VERSION 5.8 ;
BUSBITCHARS "[]" ;
DIVIDERCHAR "/" ;
UNITS
    DATABASE MICRONS 1000 ;
END UNITS

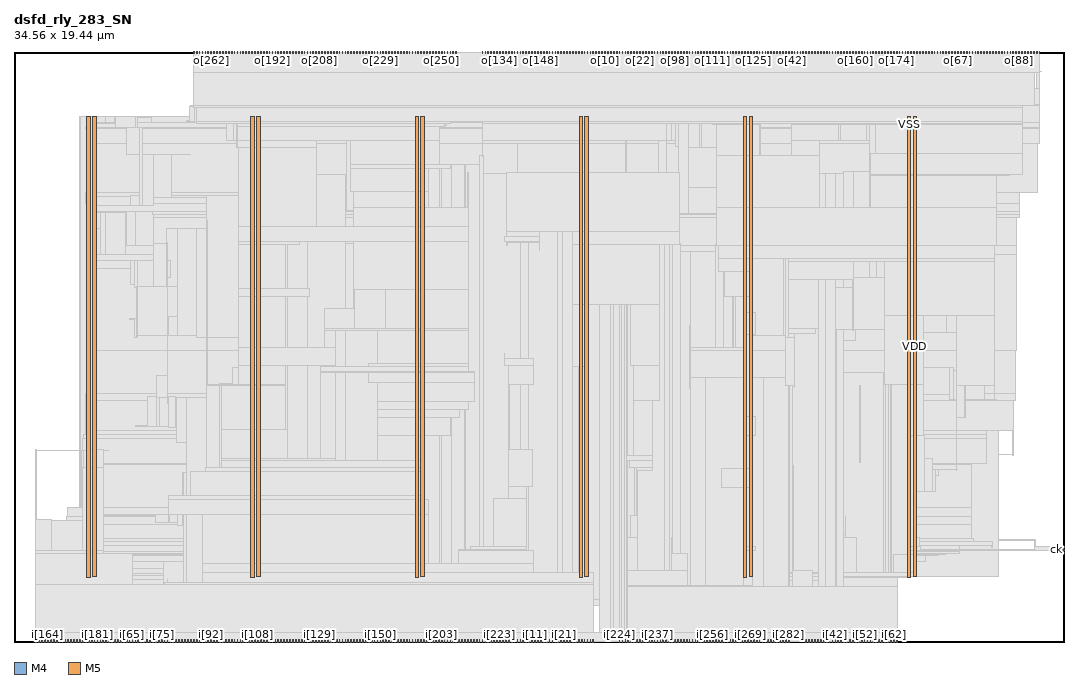
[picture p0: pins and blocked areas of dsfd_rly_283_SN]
MACRO dsfd_rly_283_SN
  FOREIGN dsfd_rly_283_SN 0 0 ;
  CLASS BLOCK ;
  SIZE 34.56 BY 19.44 ;
  PIN ck
    DIRECTION INPUT ;
    USE SIGNAL ;
    PORT
      LAYER M4 ;
        RECT  34.476 3.024 34.56 3.048 ;
    END
  END ck
  PIN i[0]
    DIRECTION INPUT ;
    USE SIGNAL ;
    PORT
      LAYER M5 ;
        RECT  16.08 0 16.104 0.084 ;
    END
  END i[0]
  PIN i[100]
    DIRECTION INPUT ;
    USE SIGNAL ;
    PORT
      LAYER M5 ;
        RECT  7.248 0 7.272 0.084 ;
    END
  END i[100]
  PIN i[101]
    DIRECTION INPUT ;
    USE SIGNAL ;
    PORT
      LAYER M5 ;
        RECT  7.344 0 7.368 0.084 ;
    END
  END i[101]
  PIN i[102]
    DIRECTION INPUT ;
    USE SIGNAL ;
    PORT
      LAYER M5 ;
        RECT  7.44 0 7.464 0.084 ;
    END
  END i[102]
  PIN i[103]
    DIRECTION INPUT ;
    USE SIGNAL ;
    PORT
      LAYER M5 ;
        RECT  7.536 0 7.56 0.084 ;
    END
  END i[103]
  PIN i[104]
    DIRECTION INPUT ;
    USE SIGNAL ;
    PORT
      LAYER M5 ;
        RECT  7.632 0 7.656 0.084 ;
    END
  END i[104]
  PIN i[105]
    DIRECTION INPUT ;
    USE SIGNAL ;
    PORT
      LAYER M5 ;
        RECT  7.728 0 7.752 0.084 ;
    END
  END i[105]
  PIN i[106]
    DIRECTION INPUT ;
    USE SIGNAL ;
    PORT
      LAYER M5 ;
        RECT  7.824 0 7.848 0.084 ;
    END
  END i[106]
  PIN i[107]
    DIRECTION INPUT ;
    USE SIGNAL ;
    PORT
      LAYER M5 ;
        RECT  7.92 0 7.944 0.084 ;
    END
  END i[107]
  PIN i[108]
    DIRECTION INPUT ;
    USE SIGNAL ;
    PORT
      LAYER M5 ;
        RECT  8.016 0 8.04 0.084 ;
    END
  END i[108]
  PIN i[109]
    DIRECTION INPUT ;
    USE SIGNAL ;
    PORT
      LAYER M5 ;
        RECT  8.112 0 8.136 0.084 ;
    END
  END i[109]
  PIN i[10]
    DIRECTION INPUT ;
    USE SIGNAL ;
    PORT
      LAYER M5 ;
        RECT  17.04 0 17.064 0.084 ;
    END
  END i[10]
  PIN i[110]
    DIRECTION INPUT ;
    USE SIGNAL ;
    PORT
      LAYER M5 ;
        RECT  8.208 0 8.232 0.084 ;
    END
  END i[110]
  PIN i[111]
    DIRECTION INPUT ;
    USE SIGNAL ;
    PORT
      LAYER M5 ;
        RECT  8.304 0 8.328 0.084 ;
    END
  END i[111]
  PIN i[112]
    DIRECTION INPUT ;
    USE SIGNAL ;
    PORT
      LAYER M5 ;
        RECT  8.4 0 8.424 0.084 ;
    END
  END i[112]
  PIN i[113]
    DIRECTION INPUT ;
    USE SIGNAL ;
    PORT
      LAYER M5 ;
        RECT  8.496 0 8.52 0.084 ;
    END
  END i[113]
  PIN i[114]
    DIRECTION INPUT ;
    USE SIGNAL ;
    PORT
      LAYER M5 ;
        RECT  8.592 0 8.616 0.084 ;
    END
  END i[114]
  PIN i[115]
    DIRECTION INPUT ;
    USE SIGNAL ;
    PORT
      LAYER M5 ;
        RECT  8.688 0 8.712 0.084 ;
    END
  END i[115]
  PIN i[116]
    DIRECTION INPUT ;
    USE SIGNAL ;
    PORT
      LAYER M5 ;
        RECT  8.784 0 8.808 0.084 ;
    END
  END i[116]
  PIN i[117]
    DIRECTION INPUT ;
    USE SIGNAL ;
    PORT
      LAYER M5 ;
        RECT  8.88 0 8.904 0.084 ;
    END
  END i[117]
  PIN i[118]
    DIRECTION INPUT ;
    USE SIGNAL ;
    PORT
      LAYER M5 ;
        RECT  8.976 0 9 0.084 ;
    END
  END i[118]
  PIN i[119]
    DIRECTION INPUT ;
    USE SIGNAL ;
    PORT
      LAYER M5 ;
        RECT  9.072 0 9.096 0.084 ;
    END
  END i[119]
  PIN i[11]
    DIRECTION INPUT ;
    USE SIGNAL ;
    PORT
      LAYER M5 ;
        RECT  17.136 0 17.16 0.084 ;
    END
  END i[11]
  PIN i[120]
    DIRECTION INPUT ;
    USE SIGNAL ;
    PORT
      LAYER M5 ;
        RECT  9.168 0 9.192 0.084 ;
    END
  END i[120]
  PIN i[121]
    DIRECTION INPUT ;
    USE SIGNAL ;
    PORT
      LAYER M5 ;
        RECT  9.264 0 9.288 0.084 ;
    END
  END i[121]
  PIN i[122]
    DIRECTION INPUT ;
    USE SIGNAL ;
    PORT
      LAYER M5 ;
        RECT  9.36 0 9.384 0.084 ;
    END
  END i[122]
  PIN i[123]
    DIRECTION INPUT ;
    USE SIGNAL ;
    PORT
      LAYER M5 ;
        RECT  9.456 0 9.48 0.084 ;
    END
  END i[123]
  PIN i[124]
    DIRECTION INPUT ;
    USE SIGNAL ;
    PORT
      LAYER M5 ;
        RECT  9.552 0 9.576 0.084 ;
    END
  END i[124]
  PIN i[125]
    DIRECTION INPUT ;
    USE SIGNAL ;
    PORT
      LAYER M5 ;
        RECT  9.648 0 9.672 0.084 ;
    END
  END i[125]
  PIN i[126]
    DIRECTION INPUT ;
    USE SIGNAL ;
    PORT
      LAYER M5 ;
        RECT  9.744 0 9.768 0.084 ;
    END
  END i[126]
  PIN i[127]
    DIRECTION INPUT ;
    USE SIGNAL ;
    PORT
      LAYER M5 ;
        RECT  9.84 0 9.864 0.084 ;
    END
  END i[127]
  PIN i[128]
    DIRECTION INPUT ;
    USE SIGNAL ;
    PORT
      LAYER M5 ;
        RECT  9.936 0 9.96 0.084 ;
    END
  END i[128]
  PIN i[129]
    DIRECTION INPUT ;
    USE SIGNAL ;
    PORT
      LAYER M5 ;
        RECT  10.032 0 10.056 0.084 ;
    END
  END i[129]
  PIN i[12]
    DIRECTION INPUT ;
    USE SIGNAL ;
    PORT
      LAYER M5 ;
        RECT  17.232 0 17.256 0.084 ;
    END
  END i[12]
  PIN i[130]
    DIRECTION INPUT ;
    USE SIGNAL ;
    PORT
      LAYER M5 ;
        RECT  10.128 0 10.152 0.084 ;
    END
  END i[130]
  PIN i[131]
    DIRECTION INPUT ;
    USE SIGNAL ;
    PORT
      LAYER M5 ;
        RECT  10.224 0 10.248 0.084 ;
    END
  END i[131]
  PIN i[132]
    DIRECTION INPUT ;
    USE SIGNAL ;
    PORT
      LAYER M5 ;
        RECT  10.32 0 10.344 0.084 ;
    END
  END i[132]
  PIN i[133]
    DIRECTION INPUT ;
    USE SIGNAL ;
    PORT
      LAYER M5 ;
        RECT  10.416 0 10.44 0.084 ;
    END
  END i[133]
  PIN i[134]
    DIRECTION INPUT ;
    USE SIGNAL ;
    PORT
      LAYER M5 ;
        RECT  10.512 0 10.536 0.084 ;
    END
  END i[134]
  PIN i[135]
    DIRECTION INPUT ;
    USE SIGNAL ;
    PORT
      LAYER M5 ;
        RECT  10.608 0 10.632 0.084 ;
    END
  END i[135]
  PIN i[136]
    DIRECTION INPUT ;
    USE SIGNAL ;
    PORT
      LAYER M5 ;
        RECT  10.704 0 10.728 0.084 ;
    END
  END i[136]
  PIN i[137]
    DIRECTION INPUT ;
    USE SIGNAL ;
    PORT
      LAYER M5 ;
        RECT  10.8 0 10.824 0.084 ;
    END
  END i[137]
  PIN i[138]
    DIRECTION INPUT ;
    USE SIGNAL ;
    PORT
      LAYER M5 ;
        RECT  10.896 0 10.92 0.084 ;
    END
  END i[138]
  PIN i[139]
    DIRECTION INPUT ;
    USE SIGNAL ;
    PORT
      LAYER M5 ;
        RECT  10.992 0 11.016 0.084 ;
    END
  END i[139]
  PIN i[13]
    DIRECTION INPUT ;
    USE SIGNAL ;
    PORT
      LAYER M5 ;
        RECT  17.328 0 17.352 0.084 ;
    END
  END i[13]
  PIN i[140]
    DIRECTION INPUT ;
    USE SIGNAL ;
    PORT
      LAYER M5 ;
        RECT  11.088 0 11.112 0.084 ;
    END
  END i[140]
  PIN i[141]
    DIRECTION INPUT ;
    USE SIGNAL ;
    PORT
      LAYER M5 ;
        RECT  11.184 0 11.208 0.084 ;
    END
  END i[141]
  PIN i[142]
    DIRECTION INPUT ;
    USE SIGNAL ;
    PORT
      LAYER M5 ;
        RECT  11.28 0 11.304 0.084 ;
    END
  END i[142]
  PIN i[143]
    DIRECTION INPUT ;
    USE SIGNAL ;
    PORT
      LAYER M5 ;
        RECT  11.376 0 11.4 0.084 ;
    END
  END i[143]
  PIN i[144]
    DIRECTION INPUT ;
    USE SIGNAL ;
    PORT
      LAYER M5 ;
        RECT  11.472 0 11.496 0.084 ;
    END
  END i[144]
  PIN i[145]
    DIRECTION INPUT ;
    USE SIGNAL ;
    PORT
      LAYER M5 ;
        RECT  11.568 0 11.592 0.084 ;
    END
  END i[145]
  PIN i[146]
    DIRECTION INPUT ;
    USE SIGNAL ;
    PORT
      LAYER M5 ;
        RECT  11.664 0 11.688 0.084 ;
    END
  END i[146]
  PIN i[147]
    DIRECTION INPUT ;
    USE SIGNAL ;
    PORT
      LAYER M5 ;
        RECT  11.76 0 11.784 0.084 ;
    END
  END i[147]
  PIN i[148]
    DIRECTION INPUT ;
    USE SIGNAL ;
    PORT
      LAYER M5 ;
        RECT  11.856 0 11.88 0.084 ;
    END
  END i[148]
  PIN i[149]
    DIRECTION INPUT ;
    USE SIGNAL ;
    PORT
      LAYER M5 ;
        RECT  11.952 0 11.976 0.084 ;
    END
  END i[149]
  PIN i[14]
    DIRECTION INPUT ;
    USE SIGNAL ;
    PORT
      LAYER M5 ;
        RECT  17.424 0 17.448 0.084 ;
    END
  END i[14]
  PIN i[150]
    DIRECTION INPUT ;
    USE SIGNAL ;
    PORT
      LAYER M5 ;
        RECT  12.048 0 12.072 0.084 ;
    END
  END i[150]
  PIN i[151]
    DIRECTION INPUT ;
    USE SIGNAL ;
    PORT
      LAYER M5 ;
        RECT  12.144 0 12.168 0.084 ;
    END
  END i[151]
  PIN i[152]
    DIRECTION INPUT ;
    USE SIGNAL ;
    PORT
      LAYER M5 ;
        RECT  12.24 0 12.264 0.084 ;
    END
  END i[152]
  PIN i[153]
    DIRECTION INPUT ;
    USE SIGNAL ;
    PORT
      LAYER M5 ;
        RECT  12.336 0 12.36 0.084 ;
    END
  END i[153]
  PIN i[154]
    DIRECTION INPUT ;
    USE SIGNAL ;
    PORT
      LAYER M5 ;
        RECT  12.432 0 12.456 0.084 ;
    END
  END i[154]
  PIN i[155]
    DIRECTION INPUT ;
    USE SIGNAL ;
    PORT
      LAYER M5 ;
        RECT  12.528 0 12.552 0.084 ;
    END
  END i[155]
  PIN i[156]
    DIRECTION INPUT ;
    USE SIGNAL ;
    PORT
      LAYER M5 ;
        RECT  12.624 0 12.648 0.084 ;
    END
  END i[156]
  PIN i[157]
    DIRECTION INPUT ;
    USE SIGNAL ;
    PORT
      LAYER M5 ;
        RECT  12.72 0 12.744 0.084 ;
    END
  END i[157]
  PIN i[158]
    DIRECTION INPUT ;
    USE SIGNAL ;
    PORT
      LAYER M5 ;
        RECT  12.816 0 12.84 0.084 ;
    END
  END i[158]
  PIN i[159]
    DIRECTION INPUT ;
    USE SIGNAL ;
    PORT
      LAYER M5 ;
        RECT  12.912 0 12.936 0.084 ;
    END
  END i[159]
  PIN i[15]
    DIRECTION INPUT ;
    USE SIGNAL ;
    PORT
      LAYER M5 ;
        RECT  17.52 0 17.544 0.084 ;
    END
  END i[15]
  PIN i[160]
    DIRECTION INPUT ;
    USE SIGNAL ;
    PORT
      LAYER M5 ;
        RECT  0.72 0 0.744 0.084 ;
    END
  END i[160]
  PIN i[161]
    DIRECTION INPUT ;
    USE SIGNAL ;
    PORT
      LAYER M5 ;
        RECT  0.816 0 0.84 0.084 ;
    END
  END i[161]
  PIN i[162]
    DIRECTION INPUT ;
    USE SIGNAL ;
    PORT
      LAYER M5 ;
        RECT  0.912 0 0.936 0.084 ;
    END
  END i[162]
  PIN i[163]
    DIRECTION INPUT ;
    USE SIGNAL ;
    PORT
      LAYER M5 ;
        RECT  1.008 0 1.032 0.084 ;
    END
  END i[163]
  PIN i[164]
    DIRECTION INPUT ;
    USE SIGNAL ;
    PORT
      LAYER M5 ;
        RECT  1.104 0 1.128 0.084 ;
    END
  END i[164]
  PIN i[165]
    DIRECTION INPUT ;
    USE SIGNAL ;
    PORT
      LAYER M5 ;
        RECT  1.2 0 1.224 0.084 ;
    END
  END i[165]
  PIN i[166]
    DIRECTION INPUT ;
    USE SIGNAL ;
    PORT
      LAYER M5 ;
        RECT  1.296 0 1.32 0.084 ;
    END
  END i[166]
  PIN i[167]
    DIRECTION INPUT ;
    USE SIGNAL ;
    PORT
      LAYER M5 ;
        RECT  1.392 0 1.416 0.084 ;
    END
  END i[167]
  PIN i[168]
    DIRECTION INPUT ;
    USE SIGNAL ;
    PORT
      LAYER M5 ;
        RECT  1.488 0 1.512 0.084 ;
    END
  END i[168]
  PIN i[169]
    DIRECTION INPUT ;
    USE SIGNAL ;
    PORT
      LAYER M5 ;
        RECT  1.584 0 1.608 0.084 ;
    END
  END i[169]
  PIN i[16]
    DIRECTION INPUT ;
    USE SIGNAL ;
    PORT
      LAYER M5 ;
        RECT  17.616 0 17.64 0.084 ;
    END
  END i[16]
  PIN i[170]
    DIRECTION INPUT ;
    USE SIGNAL ;
    PORT
      LAYER M5 ;
        RECT  1.68 0 1.704 0.084 ;
    END
  END i[170]
  PIN i[171]
    DIRECTION INPUT ;
    USE SIGNAL ;
    PORT
      LAYER M5 ;
        RECT  1.776 0 1.8 0.084 ;
    END
  END i[171]
  PIN i[172]
    DIRECTION INPUT ;
    USE SIGNAL ;
    PORT
      LAYER M5 ;
        RECT  1.872 0 1.896 0.084 ;
    END
  END i[172]
  PIN i[173]
    DIRECTION INPUT ;
    USE SIGNAL ;
    PORT
      LAYER M5 ;
        RECT  1.968 0 1.992 0.084 ;
    END
  END i[173]
  PIN i[174]
    DIRECTION INPUT ;
    USE SIGNAL ;
    PORT
      LAYER M5 ;
        RECT  2.064 0 2.088 0.084 ;
    END
  END i[174]
  PIN i[175]
    DIRECTION INPUT ;
    USE SIGNAL ;
    PORT
      LAYER M5 ;
        RECT  2.16 0 2.184 0.084 ;
    END
  END i[175]
  PIN i[176]
    DIRECTION INPUT ;
    USE SIGNAL ;
    PORT
      LAYER M5 ;
        RECT  2.256 0 2.28 0.084 ;
    END
  END i[176]
  PIN i[177]
    DIRECTION INPUT ;
    USE SIGNAL ;
    PORT
      LAYER M5 ;
        RECT  2.352 0 2.376 0.084 ;
    END
  END i[177]
  PIN i[178]
    DIRECTION INPUT ;
    USE SIGNAL ;
    PORT
      LAYER M5 ;
        RECT  2.448 0 2.472 0.084 ;
    END
  END i[178]
  PIN i[179]
    DIRECTION INPUT ;
    USE SIGNAL ;
    PORT
      LAYER M5 ;
        RECT  2.544 0 2.568 0.084 ;
    END
  END i[179]
  PIN i[17]
    DIRECTION INPUT ;
    USE SIGNAL ;
    PORT
      LAYER M5 ;
        RECT  17.712 0 17.736 0.084 ;
    END
  END i[17]
  PIN i[180]
    DIRECTION INPUT ;
    USE SIGNAL ;
    PORT
      LAYER M5 ;
        RECT  2.64 0 2.664 0.084 ;
    END
  END i[180]
  PIN i[181]
    DIRECTION INPUT ;
    USE SIGNAL ;
    PORT
      LAYER M5 ;
        RECT  2.736 0 2.76 0.084 ;
    END
  END i[181]
  PIN i[182]
    DIRECTION INPUT ;
    USE SIGNAL ;
    PORT
      LAYER M5 ;
        RECT  2.832 0 2.856 0.084 ;
    END
  END i[182]
  PIN i[183]
    DIRECTION INPUT ;
    USE SIGNAL ;
    PORT
      LAYER M5 ;
        RECT  2.928 0 2.952 0.084 ;
    END
  END i[183]
  PIN i[184]
    DIRECTION INPUT ;
    USE SIGNAL ;
    PORT
      LAYER M5 ;
        RECT  3.024 0 3.048 0.084 ;
    END
  END i[184]
  PIN i[185]
    DIRECTION INPUT ;
    USE SIGNAL ;
    PORT
      LAYER M5 ;
        RECT  3.12 0 3.144 0.084 ;
    END
  END i[185]
  PIN i[186]
    DIRECTION INPUT ;
    USE SIGNAL ;
    PORT
      LAYER M5 ;
        RECT  3.216 0 3.24 0.084 ;
    END
  END i[186]
  PIN i[187]
    DIRECTION INPUT ;
    USE SIGNAL ;
    PORT
      LAYER M5 ;
        RECT  3.312 0 3.336 0.084 ;
    END
  END i[187]
  PIN i[188]
    DIRECTION INPUT ;
    USE SIGNAL ;
    PORT
      LAYER M5 ;
        RECT  3.408 0 3.432 0.084 ;
    END
  END i[188]
  PIN i[189]
    DIRECTION INPUT ;
    USE SIGNAL ;
    PORT
      LAYER M5 ;
        RECT  3.504 0 3.528 0.084 ;
    END
  END i[189]
  PIN i[18]
    DIRECTION INPUT ;
    USE SIGNAL ;
    PORT
      LAYER M5 ;
        RECT  17.808 0 17.832 0.084 ;
    END
  END i[18]
  PIN i[190]
    DIRECTION INPUT ;
    USE SIGNAL ;
    PORT
      LAYER M5 ;
        RECT  3.6 0 3.624 0.084 ;
    END
  END i[190]
  PIN i[191]
    DIRECTION INPUT ;
    USE SIGNAL ;
    PORT
      LAYER M5 ;
        RECT  3.696 0 3.72 0.084 ;
    END
  END i[191]
  PIN i[192]
    DIRECTION INPUT ;
    USE SIGNAL ;
    PORT
      LAYER M5 ;
        RECT  13.008 0 13.032 0.084 ;
    END
  END i[192]
  PIN i[193]
    DIRECTION INPUT ;
    USE SIGNAL ;
    PORT
      LAYER M5 ;
        RECT  13.104 0 13.128 0.084 ;
    END
  END i[193]
  PIN i[194]
    DIRECTION INPUT ;
    USE SIGNAL ;
    PORT
      LAYER M5 ;
        RECT  13.2 0 13.224 0.084 ;
    END
  END i[194]
  PIN i[195]
    DIRECTION INPUT ;
    USE SIGNAL ;
    PORT
      LAYER M5 ;
        RECT  13.296 0 13.32 0.084 ;
    END
  END i[195]
  PIN i[196]
    DIRECTION INPUT ;
    USE SIGNAL ;
    PORT
      LAYER M5 ;
        RECT  13.392 0 13.416 0.084 ;
    END
  END i[196]
  PIN i[197]
    DIRECTION INPUT ;
    USE SIGNAL ;
    PORT
      LAYER M5 ;
        RECT  13.488 0 13.512 0.084 ;
    END
  END i[197]
  PIN i[198]
    DIRECTION INPUT ;
    USE SIGNAL ;
    PORT
      LAYER M5 ;
        RECT  13.584 0 13.608 0.084 ;
    END
  END i[198]
  PIN i[199]
    DIRECTION INPUT ;
    USE SIGNAL ;
    PORT
      LAYER M5 ;
        RECT  13.68 0 13.704 0.084 ;
    END
  END i[199]
  PIN i[19]
    DIRECTION INPUT ;
    USE SIGNAL ;
    PORT
      LAYER M5 ;
        RECT  17.904 0 17.928 0.084 ;
    END
  END i[19]
  PIN i[1]
    DIRECTION INPUT ;
    USE SIGNAL ;
    PORT
      LAYER M5 ;
        RECT  16.176 0 16.2 0.084 ;
    END
  END i[1]
  PIN i[200]
    DIRECTION INPUT ;
    USE SIGNAL ;
    PORT
      LAYER M5 ;
        RECT  13.776 0 13.8 0.084 ;
    END
  END i[200]
  PIN i[201]
    DIRECTION INPUT ;
    USE SIGNAL ;
    PORT
      LAYER M5 ;
        RECT  13.872 0 13.896 0.084 ;
    END
  END i[201]
  PIN i[202]
    DIRECTION INPUT ;
    USE SIGNAL ;
    PORT
      LAYER M5 ;
        RECT  13.968 0 13.992 0.084 ;
    END
  END i[202]
  PIN i[203]
    DIRECTION INPUT ;
    USE SIGNAL ;
    PORT
      LAYER M5 ;
        RECT  14.064 0 14.088 0.084 ;
    END
  END i[203]
  PIN i[204]
    DIRECTION INPUT ;
    USE SIGNAL ;
    PORT
      LAYER M5 ;
        RECT  14.16 0 14.184 0.084 ;
    END
  END i[204]
  PIN i[205]
    DIRECTION INPUT ;
    USE SIGNAL ;
    PORT
      LAYER M5 ;
        RECT  14.256 0 14.28 0.084 ;
    END
  END i[205]
  PIN i[206]
    DIRECTION INPUT ;
    USE SIGNAL ;
    PORT
      LAYER M5 ;
        RECT  14.352 0 14.376 0.084 ;
    END
  END i[206]
  PIN i[207]
    DIRECTION INPUT ;
    USE SIGNAL ;
    PORT
      LAYER M5 ;
        RECT  14.448 0 14.472 0.084 ;
    END
  END i[207]
  PIN i[208]
    DIRECTION INPUT ;
    USE SIGNAL ;
    PORT
      LAYER M5 ;
        RECT  14.544 0 14.568 0.084 ;
    END
  END i[208]
  PIN i[209]
    DIRECTION INPUT ;
    USE SIGNAL ;
    PORT
      LAYER M5 ;
        RECT  14.64 0 14.664 0.084 ;
    END
  END i[209]
  PIN i[20]
    DIRECTION INPUT ;
    USE SIGNAL ;
    PORT
      LAYER M5 ;
        RECT  18 0 18.024 0.084 ;
    END
  END i[20]
  PIN i[210]
    DIRECTION INPUT ;
    USE SIGNAL ;
    PORT
      LAYER M5 ;
        RECT  14.736 0 14.76 0.084 ;
    END
  END i[210]
  PIN i[211]
    DIRECTION INPUT ;
    USE SIGNAL ;
    PORT
      LAYER M5 ;
        RECT  14.832 0 14.856 0.084 ;
    END
  END i[211]
  PIN i[212]
    DIRECTION INPUT ;
    USE SIGNAL ;
    PORT
      LAYER M5 ;
        RECT  14.928 0 14.952 0.084 ;
    END
  END i[212]
  PIN i[213]
    DIRECTION INPUT ;
    USE SIGNAL ;
    PORT
      LAYER M5 ;
        RECT  15.024 0 15.048 0.084 ;
    END
  END i[213]
  PIN i[214]
    DIRECTION INPUT ;
    USE SIGNAL ;
    PORT
      LAYER M5 ;
        RECT  15.12 0 15.144 0.084 ;
    END
  END i[214]
  PIN i[215]
    DIRECTION INPUT ;
    USE SIGNAL ;
    PORT
      LAYER M5 ;
        RECT  15.216 0 15.24 0.084 ;
    END
  END i[215]
  PIN i[216]
    DIRECTION INPUT ;
    USE SIGNAL ;
    PORT
      LAYER M5 ;
        RECT  15.312 0 15.336 0.084 ;
    END
  END i[216]
  PIN i[217]
    DIRECTION INPUT ;
    USE SIGNAL ;
    PORT
      LAYER M5 ;
        RECT  15.408 0 15.432 0.084 ;
    END
  END i[217]
  PIN i[218]
    DIRECTION INPUT ;
    USE SIGNAL ;
    PORT
      LAYER M5 ;
        RECT  15.504 0 15.528 0.084 ;
    END
  END i[218]
  PIN i[219]
    DIRECTION INPUT ;
    USE SIGNAL ;
    PORT
      LAYER M5 ;
        RECT  15.6 0 15.624 0.084 ;
    END
  END i[219]
  PIN i[21]
    DIRECTION INPUT ;
    USE SIGNAL ;
    PORT
      LAYER M5 ;
        RECT  18.096 0 18.12 0.084 ;
    END
  END i[21]
  PIN i[220]
    DIRECTION INPUT ;
    USE SIGNAL ;
    PORT
      LAYER M5 ;
        RECT  15.696 0 15.72 0.084 ;
    END
  END i[220]
  PIN i[221]
    DIRECTION INPUT ;
    USE SIGNAL ;
    PORT
      LAYER M5 ;
        RECT  15.792 0 15.816 0.084 ;
    END
  END i[221]
  PIN i[222]
    DIRECTION INPUT ;
    USE SIGNAL ;
    PORT
      LAYER M5 ;
        RECT  15.888 0 15.912 0.084 ;
    END
  END i[222]
  PIN i[223]
    DIRECTION INPUT ;
    USE SIGNAL ;
    PORT
      LAYER M5 ;
        RECT  15.984 0 16.008 0.084 ;
    END
  END i[223]
  PIN i[224]
    DIRECTION INPUT ;
    USE SIGNAL ;
    PORT
      LAYER M5 ;
        RECT  19.92 0 19.944 0.084 ;
    END
  END i[224]
  PIN i[225]
    DIRECTION INPUT ;
    USE SIGNAL ;
    PORT
      LAYER M5 ;
        RECT  20.016 0 20.04 0.084 ;
    END
  END i[225]
  PIN i[226]
    DIRECTION INPUT ;
    USE SIGNAL ;
    PORT
      LAYER M5 ;
        RECT  20.112 0 20.136 0.084 ;
    END
  END i[226]
  PIN i[227]
    DIRECTION INPUT ;
    USE SIGNAL ;
    PORT
      LAYER M5 ;
        RECT  20.208 0 20.232 0.084 ;
    END
  END i[227]
  PIN i[228]
    DIRECTION INPUT ;
    USE SIGNAL ;
    PORT
      LAYER M5 ;
        RECT  20.304 0 20.328 0.084 ;
    END
  END i[228]
  PIN i[229]
    DIRECTION INPUT ;
    USE SIGNAL ;
    PORT
      LAYER M5 ;
        RECT  20.4 0 20.424 0.084 ;
    END
  END i[229]
  PIN i[22]
    DIRECTION INPUT ;
    USE SIGNAL ;
    PORT
      LAYER M5 ;
        RECT  18.192 0 18.216 0.084 ;
    END
  END i[22]
  PIN i[230]
    DIRECTION INPUT ;
    USE SIGNAL ;
    PORT
      LAYER M5 ;
        RECT  20.496 0 20.52 0.084 ;
    END
  END i[230]
  PIN i[231]
    DIRECTION INPUT ;
    USE SIGNAL ;
    PORT
      LAYER M5 ;
        RECT  20.592 0 20.616 0.084 ;
    END
  END i[231]
  PIN i[232]
    DIRECTION INPUT ;
    USE SIGNAL ;
    PORT
      LAYER M5 ;
        RECT  20.688 0 20.712 0.084 ;
    END
  END i[232]
  PIN i[233]
    DIRECTION INPUT ;
    USE SIGNAL ;
    PORT
      LAYER M5 ;
        RECT  20.784 0 20.808 0.084 ;
    END
  END i[233]
  PIN i[234]
    DIRECTION INPUT ;
    USE SIGNAL ;
    PORT
      LAYER M5 ;
        RECT  20.88 0 20.904 0.084 ;
    END
  END i[234]
  PIN i[235]
    DIRECTION INPUT ;
    USE SIGNAL ;
    PORT
      LAYER M5 ;
        RECT  20.976 0 21 0.084 ;
    END
  END i[235]
  PIN i[236]
    DIRECTION INPUT ;
    USE SIGNAL ;
    PORT
      LAYER M5 ;
        RECT  21.072 0 21.096 0.084 ;
    END
  END i[236]
  PIN i[237]
    DIRECTION INPUT ;
    USE SIGNAL ;
    PORT
      LAYER M5 ;
        RECT  21.168 0 21.192 0.084 ;
    END
  END i[237]
  PIN i[238]
    DIRECTION INPUT ;
    USE SIGNAL ;
    PORT
      LAYER M5 ;
        RECT  21.264 0 21.288 0.084 ;
    END
  END i[238]
  PIN i[239]
    DIRECTION INPUT ;
    USE SIGNAL ;
    PORT
      LAYER M5 ;
        RECT  21.36 0 21.384 0.084 ;
    END
  END i[239]
  PIN i[23]
    DIRECTION INPUT ;
    USE SIGNAL ;
    PORT
      LAYER M5 ;
        RECT  18.288 0 18.312 0.084 ;
    END
  END i[23]
  PIN i[240]
    DIRECTION INPUT ;
    USE SIGNAL ;
    PORT
      LAYER M5 ;
        RECT  21.456 0 21.48 0.084 ;
    END
  END i[240]
  PIN i[241]
    DIRECTION INPUT ;
    USE SIGNAL ;
    PORT
      LAYER M5 ;
        RECT  21.552 0 21.576 0.084 ;
    END
  END i[241]
  PIN i[242]
    DIRECTION INPUT ;
    USE SIGNAL ;
    PORT
      LAYER M5 ;
        RECT  21.648 0 21.672 0.084 ;
    END
  END i[242]
  PIN i[243]
    DIRECTION INPUT ;
    USE SIGNAL ;
    PORT
      LAYER M5 ;
        RECT  21.744 0 21.768 0.084 ;
    END
  END i[243]
  PIN i[244]
    DIRECTION INPUT ;
    USE SIGNAL ;
    PORT
      LAYER M5 ;
        RECT  21.84 0 21.864 0.084 ;
    END
  END i[244]
  PIN i[245]
    DIRECTION INPUT ;
    USE SIGNAL ;
    PORT
      LAYER M5 ;
        RECT  21.936 0 21.96 0.084 ;
    END
  END i[245]
  PIN i[246]
    DIRECTION INPUT ;
    USE SIGNAL ;
    PORT
      LAYER M5 ;
        RECT  22.032 0 22.056 0.084 ;
    END
  END i[246]
  PIN i[247]
    DIRECTION INPUT ;
    USE SIGNAL ;
    PORT
      LAYER M5 ;
        RECT  22.128 0 22.152 0.084 ;
    END
  END i[247]
  PIN i[248]
    DIRECTION INPUT ;
    USE SIGNAL ;
    PORT
      LAYER M5 ;
        RECT  22.224 0 22.248 0.084 ;
    END
  END i[248]
  PIN i[249]
    DIRECTION INPUT ;
    USE SIGNAL ;
    PORT
      LAYER M5 ;
        RECT  22.32 0 22.344 0.084 ;
    END
  END i[249]
  PIN i[24]
    DIRECTION INPUT ;
    USE SIGNAL ;
    PORT
      LAYER M5 ;
        RECT  18.384 0 18.408 0.084 ;
    END
  END i[24]
  PIN i[250]
    DIRECTION INPUT ;
    USE SIGNAL ;
    PORT
      LAYER M5 ;
        RECT  22.416 0 22.44 0.084 ;
    END
  END i[250]
  PIN i[251]
    DIRECTION INPUT ;
    USE SIGNAL ;
    PORT
      LAYER M5 ;
        RECT  22.512 0 22.536 0.084 ;
    END
  END i[251]
  PIN i[252]
    DIRECTION INPUT ;
    USE SIGNAL ;
    PORT
      LAYER M5 ;
        RECT  22.608 0 22.632 0.084 ;
    END
  END i[252]
  PIN i[253]
    DIRECTION INPUT ;
    USE SIGNAL ;
    PORT
      LAYER M5 ;
        RECT  22.704 0 22.728 0.084 ;
    END
  END i[253]
  PIN i[254]
    DIRECTION INPUT ;
    USE SIGNAL ;
    PORT
      LAYER M5 ;
        RECT  22.8 0 22.824 0.084 ;
    END
  END i[254]
  PIN i[255]
    DIRECTION INPUT ;
    USE SIGNAL ;
    PORT
      LAYER M5 ;
        RECT  22.896 0 22.92 0.084 ;
    END
  END i[255]
  PIN i[256]
    DIRECTION INPUT ;
    USE SIGNAL ;
    PORT
      LAYER M5 ;
        RECT  22.992 0 23.016 0.084 ;
    END
  END i[256]
  PIN i[257]
    DIRECTION INPUT ;
    USE SIGNAL ;
    PORT
      LAYER M5 ;
        RECT  23.088 0 23.112 0.084 ;
    END
  END i[257]
  PIN i[258]
    DIRECTION INPUT ;
    USE SIGNAL ;
    PORT
      LAYER M5 ;
        RECT  23.184 0 23.208 0.084 ;
    END
  END i[258]
  PIN i[259]
    DIRECTION INPUT ;
    USE SIGNAL ;
    PORT
      LAYER M5 ;
        RECT  23.28 0 23.304 0.084 ;
    END
  END i[259]
  PIN i[25]
    DIRECTION INPUT ;
    USE SIGNAL ;
    PORT
      LAYER M5 ;
        RECT  18.48 0 18.504 0.084 ;
    END
  END i[25]
  PIN i[260]
    DIRECTION INPUT ;
    USE SIGNAL ;
    PORT
      LAYER M5 ;
        RECT  23.376 0 23.4 0.084 ;
    END
  END i[260]
  PIN i[261]
    DIRECTION INPUT ;
    USE SIGNAL ;
    PORT
      LAYER M5 ;
        RECT  23.472 0 23.496 0.084 ;
    END
  END i[261]
  PIN i[262]
    DIRECTION INPUT ;
    USE SIGNAL ;
    PORT
      LAYER M5 ;
        RECT  23.568 0 23.592 0.084 ;
    END
  END i[262]
  PIN i[263]
    DIRECTION INPUT ;
    USE SIGNAL ;
    PORT
      LAYER M5 ;
        RECT  23.664 0 23.688 0.084 ;
    END
  END i[263]
  PIN i[264]
    DIRECTION INPUT ;
    USE SIGNAL ;
    PORT
      LAYER M5 ;
        RECT  23.76 0 23.784 0.084 ;
    END
  END i[264]
  PIN i[265]
    DIRECTION INPUT ;
    USE SIGNAL ;
    PORT
      LAYER M5 ;
        RECT  23.856 0 23.88 0.084 ;
    END
  END i[265]
  PIN i[266]
    DIRECTION INPUT ;
    USE SIGNAL ;
    PORT
      LAYER M5 ;
        RECT  23.952 0 23.976 0.084 ;
    END
  END i[266]
  PIN i[267]
    DIRECTION INPUT ;
    USE SIGNAL ;
    PORT
      LAYER M5 ;
        RECT  24.048 0 24.072 0.084 ;
    END
  END i[267]
  PIN i[268]
    DIRECTION INPUT ;
    USE SIGNAL ;
    PORT
      LAYER M5 ;
        RECT  24.144 0 24.168 0.084 ;
    END
  END i[268]
  PIN i[269]
    DIRECTION INPUT ;
    USE SIGNAL ;
    PORT
      LAYER M5 ;
        RECT  24.24 0 24.264 0.084 ;
    END
  END i[269]
  PIN i[26]
    DIRECTION INPUT ;
    USE SIGNAL ;
    PORT
      LAYER M5 ;
        RECT  18.576 0 18.6 0.084 ;
    END
  END i[26]
  PIN i[270]
    DIRECTION INPUT ;
    USE SIGNAL ;
    PORT
      LAYER M5 ;
        RECT  24.336 0 24.36 0.084 ;
    END
  END i[270]
  PIN i[271]
    DIRECTION INPUT ;
    USE SIGNAL ;
    PORT
      LAYER M5 ;
        RECT  24.432 0 24.456 0.084 ;
    END
  END i[271]
  PIN i[272]
    DIRECTION INPUT ;
    USE SIGNAL ;
    PORT
      LAYER M5 ;
        RECT  24.528 0 24.552 0.084 ;
    END
  END i[272]
  PIN i[273]
    DIRECTION INPUT ;
    USE SIGNAL ;
    PORT
      LAYER M5 ;
        RECT  24.624 0 24.648 0.084 ;
    END
  END i[273]
  PIN i[274]
    DIRECTION INPUT ;
    USE SIGNAL ;
    PORT
      LAYER M5 ;
        RECT  24.72 0 24.744 0.084 ;
    END
  END i[274]
  PIN i[275]
    DIRECTION INPUT ;
    USE SIGNAL ;
    PORT
      LAYER M5 ;
        RECT  24.816 0 24.84 0.084 ;
    END
  END i[275]
  PIN i[276]
    DIRECTION INPUT ;
    USE SIGNAL ;
    PORT
      LAYER M5 ;
        RECT  24.912 0 24.936 0.084 ;
    END
  END i[276]
  PIN i[277]
    DIRECTION INPUT ;
    USE SIGNAL ;
    PORT
      LAYER M5 ;
        RECT  25.008 0 25.032 0.084 ;
    END
  END i[277]
  PIN i[278]
    DIRECTION INPUT ;
    USE SIGNAL ;
    PORT
      LAYER M5 ;
        RECT  25.104 0 25.128 0.084 ;
    END
  END i[278]
  PIN i[279]
    DIRECTION INPUT ;
    USE SIGNAL ;
    PORT
      LAYER M5 ;
        RECT  25.2 0 25.224 0.084 ;
    END
  END i[279]
  PIN i[27]
    DIRECTION INPUT ;
    USE SIGNAL ;
    PORT
      LAYER M5 ;
        RECT  18.672 0 18.696 0.084 ;
    END
  END i[27]
  PIN i[280]
    DIRECTION INPUT ;
    USE SIGNAL ;
    PORT
      LAYER M5 ;
        RECT  25.296 0 25.32 0.084 ;
    END
  END i[280]
  PIN i[281]
    DIRECTION INPUT ;
    USE SIGNAL ;
    PORT
      LAYER M5 ;
        RECT  25.392 0 25.416 0.084 ;
    END
  END i[281]
  PIN i[282]
    DIRECTION INPUT ;
    USE SIGNAL ;
    PORT
      LAYER M5 ;
        RECT  25.488 0 25.512 0.084 ;
    END
  END i[282]
  PIN i[28]
    DIRECTION INPUT ;
    USE SIGNAL ;
    PORT
      LAYER M5 ;
        RECT  18.768 0 18.792 0.084 ;
    END
  END i[28]
  PIN i[29]
    DIRECTION INPUT ;
    USE SIGNAL ;
    PORT
      LAYER M5 ;
        RECT  18.864 0 18.888 0.084 ;
    END
  END i[29]
  PIN i[2]
    DIRECTION INPUT ;
    USE SIGNAL ;
    PORT
      LAYER M5 ;
        RECT  16.272 0 16.296 0.084 ;
    END
  END i[2]
  PIN i[30]
    DIRECTION INPUT ;
    USE SIGNAL ;
    PORT
      LAYER M5 ;
        RECT  18.96 0 18.984 0.084 ;
    END
  END i[30]
  PIN i[31]
    DIRECTION INPUT ;
    USE SIGNAL ;
    PORT
      LAYER M5 ;
        RECT  19.056 0 19.08 0.084 ;
    END
  END i[31]
  PIN i[32]
    DIRECTION INPUT ;
    USE SIGNAL ;
    PORT
      LAYER M5 ;
        RECT  26.064 0 26.088 0.084 ;
    END
  END i[32]
  PIN i[33]
    DIRECTION INPUT ;
    USE SIGNAL ;
    PORT
      LAYER M5 ;
        RECT  26.16 0 26.184 0.084 ;
    END
  END i[33]
  PIN i[34]
    DIRECTION INPUT ;
    USE SIGNAL ;
    PORT
      LAYER M5 ;
        RECT  26.256 0 26.28 0.084 ;
    END
  END i[34]
  PIN i[35]
    DIRECTION INPUT ;
    USE SIGNAL ;
    PORT
      LAYER M5 ;
        RECT  26.352 0 26.376 0.084 ;
    END
  END i[35]
  PIN i[36]
    DIRECTION INPUT ;
    USE SIGNAL ;
    PORT
      LAYER M5 ;
        RECT  26.448 0 26.472 0.084 ;
    END
  END i[36]
  PIN i[37]
    DIRECTION INPUT ;
    USE SIGNAL ;
    PORT
      LAYER M5 ;
        RECT  26.544 0 26.568 0.084 ;
    END
  END i[37]
  PIN i[38]
    DIRECTION INPUT ;
    USE SIGNAL ;
    PORT
      LAYER M5 ;
        RECT  26.64 0 26.664 0.084 ;
    END
  END i[38]
  PIN i[39]
    DIRECTION INPUT ;
    USE SIGNAL ;
    PORT
      LAYER M5 ;
        RECT  26.736 0 26.76 0.084 ;
    END
  END i[39]
  PIN i[3]
    DIRECTION INPUT ;
    USE SIGNAL ;
    PORT
      LAYER M5 ;
        RECT  16.368 0 16.392 0.084 ;
    END
  END i[3]
  PIN i[40]
    DIRECTION INPUT ;
    USE SIGNAL ;
    PORT
      LAYER M5 ;
        RECT  26.832 0 26.856 0.084 ;
    END
  END i[40]
  PIN i[41]
    DIRECTION INPUT ;
    USE SIGNAL ;
    PORT
      LAYER M5 ;
        RECT  26.928 0 26.952 0.084 ;
    END
  END i[41]
  PIN i[42]
    DIRECTION INPUT ;
    USE SIGNAL ;
    PORT
      LAYER M5 ;
        RECT  27.024 0 27.048 0.084 ;
    END
  END i[42]
  PIN i[43]
    DIRECTION INPUT ;
    USE SIGNAL ;
    PORT
      LAYER M5 ;
        RECT  27.12 0 27.144 0.084 ;
    END
  END i[43]
  PIN i[44]
    DIRECTION INPUT ;
    USE SIGNAL ;
    PORT
      LAYER M5 ;
        RECT  27.216 0 27.24 0.084 ;
    END
  END i[44]
  PIN i[45]
    DIRECTION INPUT ;
    USE SIGNAL ;
    PORT
      LAYER M5 ;
        RECT  27.312 0 27.336 0.084 ;
    END
  END i[45]
  PIN i[46]
    DIRECTION INPUT ;
    USE SIGNAL ;
    PORT
      LAYER M5 ;
        RECT  27.408 0 27.432 0.084 ;
    END
  END i[46]
  PIN i[47]
    DIRECTION INPUT ;
    USE SIGNAL ;
    PORT
      LAYER M5 ;
        RECT  27.504 0 27.528 0.084 ;
    END
  END i[47]
  PIN i[48]
    DIRECTION INPUT ;
    USE SIGNAL ;
    PORT
      LAYER M5 ;
        RECT  27.6 0 27.624 0.084 ;
    END
  END i[48]
  PIN i[49]
    DIRECTION INPUT ;
    USE SIGNAL ;
    PORT
      LAYER M5 ;
        RECT  27.696 0 27.72 0.084 ;
    END
  END i[49]
  PIN i[4]
    DIRECTION INPUT ;
    USE SIGNAL ;
    PORT
      LAYER M5 ;
        RECT  16.464 0 16.488 0.084 ;
    END
  END i[4]
  PIN i[50]
    DIRECTION INPUT ;
    USE SIGNAL ;
    PORT
      LAYER M5 ;
        RECT  27.792 0 27.816 0.084 ;
    END
  END i[50]
  PIN i[51]
    DIRECTION INPUT ;
    USE SIGNAL ;
    PORT
      LAYER M5 ;
        RECT  27.888 0 27.912 0.084 ;
    END
  END i[51]
  PIN i[52]
    DIRECTION INPUT ;
    USE SIGNAL ;
    PORT
      LAYER M5 ;
        RECT  27.984 0 28.008 0.084 ;
    END
  END i[52]
  PIN i[53]
    DIRECTION INPUT ;
    USE SIGNAL ;
    PORT
      LAYER M5 ;
        RECT  28.08 0 28.104 0.084 ;
    END
  END i[53]
  PIN i[54]
    DIRECTION INPUT ;
    USE SIGNAL ;
    PORT
      LAYER M5 ;
        RECT  28.176 0 28.2 0.084 ;
    END
  END i[54]
  PIN i[55]
    DIRECTION INPUT ;
    USE SIGNAL ;
    PORT
      LAYER M5 ;
        RECT  28.272 0 28.296 0.084 ;
    END
  END i[55]
  PIN i[56]
    DIRECTION INPUT ;
    USE SIGNAL ;
    PORT
      LAYER M5 ;
        RECT  28.368 0 28.392 0.084 ;
    END
  END i[56]
  PIN i[57]
    DIRECTION INPUT ;
    USE SIGNAL ;
    PORT
      LAYER M5 ;
        RECT  28.464 0 28.488 0.084 ;
    END
  END i[57]
  PIN i[58]
    DIRECTION INPUT ;
    USE SIGNAL ;
    PORT
      LAYER M5 ;
        RECT  28.56 0 28.584 0.084 ;
    END
  END i[58]
  PIN i[59]
    DIRECTION INPUT ;
    USE SIGNAL ;
    PORT
      LAYER M5 ;
        RECT  28.656 0 28.68 0.084 ;
    END
  END i[59]
  PIN i[5]
    DIRECTION INPUT ;
    USE SIGNAL ;
    PORT
      LAYER M5 ;
        RECT  16.56 0 16.584 0.084 ;
    END
  END i[5]
  PIN i[60]
    DIRECTION INPUT ;
    USE SIGNAL ;
    PORT
      LAYER M5 ;
        RECT  28.752 0 28.776 0.084 ;
    END
  END i[60]
  PIN i[61]
    DIRECTION INPUT ;
    USE SIGNAL ;
    PORT
      LAYER M5 ;
        RECT  28.848 0 28.872 0.084 ;
    END
  END i[61]
  PIN i[62]
    DIRECTION INPUT ;
    USE SIGNAL ;
    PORT
      LAYER M5 ;
        RECT  28.944 0 28.968 0.084 ;
    END
  END i[62]
  PIN i[63]
    DIRECTION INPUT ;
    USE SIGNAL ;
    PORT
      LAYER M5 ;
        RECT  29.04 0 29.064 0.084 ;
    END
  END i[63]
  PIN i[64]
    DIRECTION INPUT ;
    USE SIGNAL ;
    PORT
      LAYER M5 ;
        RECT  3.792 0 3.816 0.084 ;
    END
  END i[64]
  PIN i[65]
    DIRECTION INPUT ;
    USE SIGNAL ;
    PORT
      LAYER M5 ;
        RECT  3.888 0 3.912 0.084 ;
    END
  END i[65]
  PIN i[66]
    DIRECTION INPUT ;
    USE SIGNAL ;
    PORT
      LAYER M5 ;
        RECT  3.984 0 4.008 0.084 ;
    END
  END i[66]
  PIN i[67]
    DIRECTION INPUT ;
    USE SIGNAL ;
    PORT
      LAYER M5 ;
        RECT  4.08 0 4.104 0.084 ;
    END
  END i[67]
  PIN i[68]
    DIRECTION INPUT ;
    USE SIGNAL ;
    PORT
      LAYER M5 ;
        RECT  4.176 0 4.2 0.084 ;
    END
  END i[68]
  PIN i[69]
    DIRECTION INPUT ;
    USE SIGNAL ;
    PORT
      LAYER M5 ;
        RECT  4.272 0 4.296 0.084 ;
    END
  END i[69]
  PIN i[6]
    DIRECTION INPUT ;
    USE SIGNAL ;
    PORT
      LAYER M5 ;
        RECT  16.656 0 16.68 0.084 ;
    END
  END i[6]
  PIN i[70]
    DIRECTION INPUT ;
    USE SIGNAL ;
    PORT
      LAYER M5 ;
        RECT  4.368 0 4.392 0.084 ;
    END
  END i[70]
  PIN i[71]
    DIRECTION INPUT ;
    USE SIGNAL ;
    PORT
      LAYER M5 ;
        RECT  4.464 0 4.488 0.084 ;
    END
  END i[71]
  PIN i[72]
    DIRECTION INPUT ;
    USE SIGNAL ;
    PORT
      LAYER M5 ;
        RECT  4.56 0 4.584 0.084 ;
    END
  END i[72]
  PIN i[73]
    DIRECTION INPUT ;
    USE SIGNAL ;
    PORT
      LAYER M5 ;
        RECT  4.656 0 4.68 0.084 ;
    END
  END i[73]
  PIN i[74]
    DIRECTION INPUT ;
    USE SIGNAL ;
    PORT
      LAYER M5 ;
        RECT  4.752 0 4.776 0.084 ;
    END
  END i[74]
  PIN i[75]
    DIRECTION INPUT ;
    USE SIGNAL ;
    PORT
      LAYER M5 ;
        RECT  4.848 0 4.872 0.084 ;
    END
  END i[75]
  PIN i[76]
    DIRECTION INPUT ;
    USE SIGNAL ;
    PORT
      LAYER M5 ;
        RECT  4.944 0 4.968 0.084 ;
    END
  END i[76]
  PIN i[77]
    DIRECTION INPUT ;
    USE SIGNAL ;
    PORT
      LAYER M5 ;
        RECT  5.04 0 5.064 0.084 ;
    END
  END i[77]
  PIN i[78]
    DIRECTION INPUT ;
    USE SIGNAL ;
    PORT
      LAYER M5 ;
        RECT  5.136 0 5.16 0.084 ;
    END
  END i[78]
  PIN i[79]
    DIRECTION INPUT ;
    USE SIGNAL ;
    PORT
      LAYER M5 ;
        RECT  5.232 0 5.256 0.084 ;
    END
  END i[79]
  PIN i[7]
    DIRECTION INPUT ;
    USE SIGNAL ;
    PORT
      LAYER M5 ;
        RECT  16.752 0 16.776 0.084 ;
    END
  END i[7]
  PIN i[80]
    DIRECTION INPUT ;
    USE SIGNAL ;
    PORT
      LAYER M5 ;
        RECT  5.328 0 5.352 0.084 ;
    END
  END i[80]
  PIN i[81]
    DIRECTION INPUT ;
    USE SIGNAL ;
    PORT
      LAYER M5 ;
        RECT  5.424 0 5.448 0.084 ;
    END
  END i[81]
  PIN i[82]
    DIRECTION INPUT ;
    USE SIGNAL ;
    PORT
      LAYER M5 ;
        RECT  5.52 0 5.544 0.084 ;
    END
  END i[82]
  PIN i[83]
    DIRECTION INPUT ;
    USE SIGNAL ;
    PORT
      LAYER M5 ;
        RECT  5.616 0 5.64 0.084 ;
    END
  END i[83]
  PIN i[84]
    DIRECTION INPUT ;
    USE SIGNAL ;
    PORT
      LAYER M5 ;
        RECT  5.712 0 5.736 0.084 ;
    END
  END i[84]
  PIN i[85]
    DIRECTION INPUT ;
    USE SIGNAL ;
    PORT
      LAYER M5 ;
        RECT  5.808 0 5.832 0.084 ;
    END
  END i[85]
  PIN i[86]
    DIRECTION INPUT ;
    USE SIGNAL ;
    PORT
      LAYER M5 ;
        RECT  5.904 0 5.928 0.084 ;
    END
  END i[86]
  PIN i[87]
    DIRECTION INPUT ;
    USE SIGNAL ;
    PORT
      LAYER M5 ;
        RECT  6 0 6.024 0.084 ;
    END
  END i[87]
  PIN i[88]
    DIRECTION INPUT ;
    USE SIGNAL ;
    PORT
      LAYER M5 ;
        RECT  6.096 0 6.12 0.084 ;
    END
  END i[88]
  PIN i[89]
    DIRECTION INPUT ;
    USE SIGNAL ;
    PORT
      LAYER M5 ;
        RECT  6.192 0 6.216 0.084 ;
    END
  END i[89]
  PIN i[8]
    DIRECTION INPUT ;
    USE SIGNAL ;
    PORT
      LAYER M5 ;
        RECT  16.848 0 16.872 0.084 ;
    END
  END i[8]
  PIN i[90]
    DIRECTION INPUT ;
    USE SIGNAL ;
    PORT
      LAYER M5 ;
        RECT  6.288 0 6.312 0.084 ;
    END
  END i[90]
  PIN i[91]
    DIRECTION INPUT ;
    USE SIGNAL ;
    PORT
      LAYER M5 ;
        RECT  6.384 0 6.408 0.084 ;
    END
  END i[91]
  PIN i[92]
    DIRECTION INPUT ;
    USE SIGNAL ;
    PORT
      LAYER M5 ;
        RECT  6.48 0 6.504 0.084 ;
    END
  END i[92]
  PIN i[93]
    DIRECTION INPUT ;
    USE SIGNAL ;
    PORT
      LAYER M5 ;
        RECT  6.576 0 6.6 0.084 ;
    END
  END i[93]
  PIN i[94]
    DIRECTION INPUT ;
    USE SIGNAL ;
    PORT
      LAYER M5 ;
        RECT  6.672 0 6.696 0.084 ;
    END
  END i[94]
  PIN i[95]
    DIRECTION INPUT ;
    USE SIGNAL ;
    PORT
      LAYER M5 ;
        RECT  6.768 0 6.792 0.084 ;
    END
  END i[95]
  PIN i[96]
    DIRECTION INPUT ;
    USE SIGNAL ;
    PORT
      LAYER M5 ;
        RECT  6.864 0 6.888 0.084 ;
    END
  END i[96]
  PIN i[97]
    DIRECTION INPUT ;
    USE SIGNAL ;
    PORT
      LAYER M5 ;
        RECT  6.96 0 6.984 0.084 ;
    END
  END i[97]
  PIN i[98]
    DIRECTION INPUT ;
    USE SIGNAL ;
    PORT
      LAYER M5 ;
        RECT  7.056 0 7.08 0.084 ;
    END
  END i[98]
  PIN i[99]
    DIRECTION INPUT ;
    USE SIGNAL ;
    PORT
      LAYER M5 ;
        RECT  7.152 0 7.176 0.084 ;
    END
  END i[99]
  PIN i[9]
    DIRECTION INPUT ;
    USE SIGNAL ;
    PORT
      LAYER M5 ;
        RECT  16.944 0 16.968 0.084 ;
    END
  END i[9]
  PIN o[0]
    DIRECTION OUTPUT ;
    USE SIGNAL ;
    PORT
      LAYER M5 ;
        RECT  18.48 19.356 18.504 19.44 ;
    END
  END o[0]
  PIN o[100]
    DIRECTION OUTPUT ;
    USE SIGNAL ;
    PORT
      LAYER M5 ;
        RECT  21.936 19.356 21.96 19.44 ;
    END
  END o[100]
  PIN o[101]
    DIRECTION OUTPUT ;
    USE SIGNAL ;
    PORT
      LAYER M5 ;
        RECT  22.032 19.356 22.056 19.44 ;
    END
  END o[101]
  PIN o[102]
    DIRECTION OUTPUT ;
    USE SIGNAL ;
    PORT
      LAYER M5 ;
        RECT  22.128 19.356 22.152 19.44 ;
    END
  END o[102]
  PIN o[103]
    DIRECTION OUTPUT ;
    USE SIGNAL ;
    PORT
      LAYER M5 ;
        RECT  22.224 19.356 22.248 19.44 ;
    END
  END o[103]
  PIN o[104]
    DIRECTION OUTPUT ;
    USE SIGNAL ;
    PORT
      LAYER M5 ;
        RECT  22.32 19.356 22.344 19.44 ;
    END
  END o[104]
  PIN o[105]
    DIRECTION OUTPUT ;
    USE SIGNAL ;
    PORT
      LAYER M5 ;
        RECT  22.416 19.356 22.44 19.44 ;
    END
  END o[105]
  PIN o[106]
    DIRECTION OUTPUT ;
    USE SIGNAL ;
    PORT
      LAYER M5 ;
        RECT  22.512 19.356 22.536 19.44 ;
    END
  END o[106]
  PIN o[107]
    DIRECTION OUTPUT ;
    USE SIGNAL ;
    PORT
      LAYER M5 ;
        RECT  22.608 19.356 22.632 19.44 ;
    END
  END o[107]
  PIN o[108]
    DIRECTION OUTPUT ;
    USE SIGNAL ;
    PORT
      LAYER M5 ;
        RECT  22.704 19.356 22.728 19.44 ;
    END
  END o[108]
  PIN o[109]
    DIRECTION OUTPUT ;
    USE SIGNAL ;
    PORT
      LAYER M5 ;
        RECT  22.8 19.356 22.824 19.44 ;
    END
  END o[109]
  PIN o[10]
    DIRECTION OUTPUT ;
    USE SIGNAL ;
    PORT
      LAYER M5 ;
        RECT  19.44 19.356 19.464 19.44 ;
    END
  END o[10]
  PIN o[110]
    DIRECTION OUTPUT ;
    USE SIGNAL ;
    PORT
      LAYER M5 ;
        RECT  22.896 19.356 22.92 19.44 ;
    END
  END o[110]
  PIN o[111]
    DIRECTION OUTPUT ;
    USE SIGNAL ;
    PORT
      LAYER M5 ;
        RECT  22.992 19.356 23.016 19.44 ;
    END
  END o[111]
  PIN o[112]
    DIRECTION OUTPUT ;
    USE SIGNAL ;
    PORT
      LAYER M5 ;
        RECT  23.088 19.356 23.112 19.44 ;
    END
  END o[112]
  PIN o[113]
    DIRECTION OUTPUT ;
    USE SIGNAL ;
    PORT
      LAYER M5 ;
        RECT  23.184 19.356 23.208 19.44 ;
    END
  END o[113]
  PIN o[114]
    DIRECTION OUTPUT ;
    USE SIGNAL ;
    PORT
      LAYER M5 ;
        RECT  23.28 19.356 23.304 19.44 ;
    END
  END o[114]
  PIN o[115]
    DIRECTION OUTPUT ;
    USE SIGNAL ;
    PORT
      LAYER M5 ;
        RECT  23.376 19.356 23.4 19.44 ;
    END
  END o[115]
  PIN o[116]
    DIRECTION OUTPUT ;
    USE SIGNAL ;
    PORT
      LAYER M5 ;
        RECT  23.472 19.356 23.496 19.44 ;
    END
  END o[116]
  PIN o[117]
    DIRECTION OUTPUT ;
    USE SIGNAL ;
    PORT
      LAYER M5 ;
        RECT  23.568 19.356 23.592 19.44 ;
    END
  END o[117]
  PIN o[118]
    DIRECTION OUTPUT ;
    USE SIGNAL ;
    PORT
      LAYER M5 ;
        RECT  23.664 19.356 23.688 19.44 ;
    END
  END o[118]
  PIN o[119]
    DIRECTION OUTPUT ;
    USE SIGNAL ;
    PORT
      LAYER M5 ;
        RECT  23.76 19.356 23.784 19.44 ;
    END
  END o[119]
  PIN o[11]
    DIRECTION OUTPUT ;
    USE SIGNAL ;
    PORT
      LAYER M5 ;
        RECT  19.536 19.356 19.56 19.44 ;
    END
  END o[11]
  PIN o[120]
    DIRECTION OUTPUT ;
    USE SIGNAL ;
    PORT
      LAYER M5 ;
        RECT  23.856 19.356 23.88 19.44 ;
    END
  END o[120]
  PIN o[121]
    DIRECTION OUTPUT ;
    USE SIGNAL ;
    PORT
      LAYER M5 ;
        RECT  23.952 19.356 23.976 19.44 ;
    END
  END o[121]
  PIN o[122]
    DIRECTION OUTPUT ;
    USE SIGNAL ;
    PORT
      LAYER M5 ;
        RECT  24.048 19.356 24.072 19.44 ;
    END
  END o[122]
  PIN o[123]
    DIRECTION OUTPUT ;
    USE SIGNAL ;
    PORT
      LAYER M5 ;
        RECT  24.144 19.356 24.168 19.44 ;
    END
  END o[123]
  PIN o[124]
    DIRECTION OUTPUT ;
    USE SIGNAL ;
    PORT
      LAYER M5 ;
        RECT  24.24 19.356 24.264 19.44 ;
    END
  END o[124]
  PIN o[125]
    DIRECTION OUTPUT ;
    USE SIGNAL ;
    PORT
      LAYER M5 ;
        RECT  24.336 19.356 24.36 19.44 ;
    END
  END o[125]
  PIN o[126]
    DIRECTION OUTPUT ;
    USE SIGNAL ;
    PORT
      LAYER M5 ;
        RECT  24.432 19.356 24.456 19.44 ;
    END
  END o[126]
  PIN o[127]
    DIRECTION OUTPUT ;
    USE SIGNAL ;
    PORT
      LAYER M5 ;
        RECT  24.528 19.356 24.552 19.44 ;
    END
  END o[127]
  PIN o[128]
    DIRECTION OUTPUT ;
    USE SIGNAL ;
    PORT
      LAYER M5 ;
        RECT  15.408 19.356 15.432 19.44 ;
    END
  END o[128]
  PIN o[129]
    DIRECTION OUTPUT ;
    USE SIGNAL ;
    PORT
      LAYER M5 ;
        RECT  15.504 19.356 15.528 19.44 ;
    END
  END o[129]
  PIN o[12]
    DIRECTION OUTPUT ;
    USE SIGNAL ;
    PORT
      LAYER M5 ;
        RECT  19.632 19.356 19.656 19.44 ;
    END
  END o[12]
  PIN o[130]
    DIRECTION OUTPUT ;
    USE SIGNAL ;
    PORT
      LAYER M5 ;
        RECT  15.6 19.356 15.624 19.44 ;
    END
  END o[130]
  PIN o[131]
    DIRECTION OUTPUT ;
    USE SIGNAL ;
    PORT
      LAYER M5 ;
        RECT  15.696 19.356 15.72 19.44 ;
    END
  END o[131]
  PIN o[132]
    DIRECTION OUTPUT ;
    USE SIGNAL ;
    PORT
      LAYER M5 ;
        RECT  15.792 19.356 15.816 19.44 ;
    END
  END o[132]
  PIN o[133]
    DIRECTION OUTPUT ;
    USE SIGNAL ;
    PORT
      LAYER M5 ;
        RECT  15.888 19.356 15.912 19.44 ;
    END
  END o[133]
  PIN o[134]
    DIRECTION OUTPUT ;
    USE SIGNAL ;
    PORT
      LAYER M5 ;
        RECT  15.984 19.356 16.008 19.44 ;
    END
  END o[134]
  PIN o[135]
    DIRECTION OUTPUT ;
    USE SIGNAL ;
    PORT
      LAYER M5 ;
        RECT  16.08 19.356 16.104 19.44 ;
    END
  END o[135]
  PIN o[136]
    DIRECTION OUTPUT ;
    USE SIGNAL ;
    PORT
      LAYER M5 ;
        RECT  16.176 19.356 16.2 19.44 ;
    END
  END o[136]
  PIN o[137]
    DIRECTION OUTPUT ;
    USE SIGNAL ;
    PORT
      LAYER M5 ;
        RECT  16.272 19.356 16.296 19.44 ;
    END
  END o[137]
  PIN o[138]
    DIRECTION OUTPUT ;
    USE SIGNAL ;
    PORT
      LAYER M5 ;
        RECT  16.368 19.356 16.392 19.44 ;
    END
  END o[138]
  PIN o[139]
    DIRECTION OUTPUT ;
    USE SIGNAL ;
    PORT
      LAYER M5 ;
        RECT  16.464 19.356 16.488 19.44 ;
    END
  END o[139]
  PIN o[13]
    DIRECTION OUTPUT ;
    USE SIGNAL ;
    PORT
      LAYER M5 ;
        RECT  19.728 19.356 19.752 19.44 ;
    END
  END o[13]
  PIN o[140]
    DIRECTION OUTPUT ;
    USE SIGNAL ;
    PORT
      LAYER M5 ;
        RECT  16.56 19.356 16.584 19.44 ;
    END
  END o[140]
  PIN o[141]
    DIRECTION OUTPUT ;
    USE SIGNAL ;
    PORT
      LAYER M5 ;
        RECT  16.656 19.356 16.68 19.44 ;
    END
  END o[141]
  PIN o[142]
    DIRECTION OUTPUT ;
    USE SIGNAL ;
    PORT
      LAYER M5 ;
        RECT  16.752 19.356 16.776 19.44 ;
    END
  END o[142]
  PIN o[143]
    DIRECTION OUTPUT ;
    USE SIGNAL ;
    PORT
      LAYER M5 ;
        RECT  16.848 19.356 16.872 19.44 ;
    END
  END o[143]
  PIN o[144]
    DIRECTION OUTPUT ;
    USE SIGNAL ;
    PORT
      LAYER M5 ;
        RECT  16.944 19.356 16.968 19.44 ;
    END
  END o[144]
  PIN o[145]
    DIRECTION OUTPUT ;
    USE SIGNAL ;
    PORT
      LAYER M5 ;
        RECT  17.04 19.356 17.064 19.44 ;
    END
  END o[145]
  PIN o[146]
    DIRECTION OUTPUT ;
    USE SIGNAL ;
    PORT
      LAYER M5 ;
        RECT  17.136 19.356 17.16 19.44 ;
    END
  END o[146]
  PIN o[147]
    DIRECTION OUTPUT ;
    USE SIGNAL ;
    PORT
      LAYER M5 ;
        RECT  17.232 19.356 17.256 19.44 ;
    END
  END o[147]
  PIN o[148]
    DIRECTION OUTPUT ;
    USE SIGNAL ;
    PORT
      LAYER M5 ;
        RECT  17.328 19.356 17.352 19.44 ;
    END
  END o[148]
  PIN o[149]
    DIRECTION OUTPUT ;
    USE SIGNAL ;
    PORT
      LAYER M5 ;
        RECT  17.424 19.356 17.448 19.44 ;
    END
  END o[149]
  PIN o[14]
    DIRECTION OUTPUT ;
    USE SIGNAL ;
    PORT
      LAYER M5 ;
        RECT  19.824 19.356 19.848 19.44 ;
    END
  END o[14]
  PIN o[150]
    DIRECTION OUTPUT ;
    USE SIGNAL ;
    PORT
      LAYER M5 ;
        RECT  17.52 19.356 17.544 19.44 ;
    END
  END o[150]
  PIN o[151]
    DIRECTION OUTPUT ;
    USE SIGNAL ;
    PORT
      LAYER M5 ;
        RECT  17.616 19.356 17.64 19.44 ;
    END
  END o[151]
  PIN o[152]
    DIRECTION OUTPUT ;
    USE SIGNAL ;
    PORT
      LAYER M5 ;
        RECT  17.712 19.356 17.736 19.44 ;
    END
  END o[152]
  PIN o[153]
    DIRECTION OUTPUT ;
    USE SIGNAL ;
    PORT
      LAYER M5 ;
        RECT  17.808 19.356 17.832 19.44 ;
    END
  END o[153]
  PIN o[154]
    DIRECTION OUTPUT ;
    USE SIGNAL ;
    PORT
      LAYER M5 ;
        RECT  17.904 19.356 17.928 19.44 ;
    END
  END o[154]
  PIN o[155]
    DIRECTION OUTPUT ;
    USE SIGNAL ;
    PORT
      LAYER M5 ;
        RECT  18 19.356 18.024 19.44 ;
    END
  END o[155]
  PIN o[156]
    DIRECTION OUTPUT ;
    USE SIGNAL ;
    PORT
      LAYER M5 ;
        RECT  18.096 19.356 18.12 19.44 ;
    END
  END o[156]
  PIN o[157]
    DIRECTION OUTPUT ;
    USE SIGNAL ;
    PORT
      LAYER M5 ;
        RECT  18.192 19.356 18.216 19.44 ;
    END
  END o[157]
  PIN o[158]
    DIRECTION OUTPUT ;
    USE SIGNAL ;
    PORT
      LAYER M5 ;
        RECT  18.288 19.356 18.312 19.44 ;
    END
  END o[158]
  PIN o[159]
    DIRECTION OUTPUT ;
    USE SIGNAL ;
    PORT
      LAYER M5 ;
        RECT  18.384 19.356 18.408 19.44 ;
    END
  END o[159]
  PIN o[15]
    DIRECTION OUTPUT ;
    USE SIGNAL ;
    PORT
      LAYER M5 ;
        RECT  19.92 19.356 19.944 19.44 ;
    END
  END o[15]
  PIN o[160]
    DIRECTION OUTPUT ;
    USE SIGNAL ;
    PORT
      LAYER M5 ;
        RECT  27.696 19.356 27.72 19.44 ;
    END
  END o[160]
  PIN o[161]
    DIRECTION OUTPUT ;
    USE SIGNAL ;
    PORT
      LAYER M5 ;
        RECT  27.792 19.356 27.816 19.44 ;
    END
  END o[161]
  PIN o[162]
    DIRECTION OUTPUT ;
    USE SIGNAL ;
    PORT
      LAYER M5 ;
        RECT  27.888 19.356 27.912 19.44 ;
    END
  END o[162]
  PIN o[163]
    DIRECTION OUTPUT ;
    USE SIGNAL ;
    PORT
      LAYER M5 ;
        RECT  27.984 19.356 28.008 19.44 ;
    END
  END o[163]
  PIN o[164]
    DIRECTION OUTPUT ;
    USE SIGNAL ;
    PORT
      LAYER M5 ;
        RECT  28.08 19.356 28.104 19.44 ;
    END
  END o[164]
  PIN o[165]
    DIRECTION OUTPUT ;
    USE SIGNAL ;
    PORT
      LAYER M5 ;
        RECT  28.176 19.356 28.2 19.44 ;
    END
  END o[165]
  PIN o[166]
    DIRECTION OUTPUT ;
    USE SIGNAL ;
    PORT
      LAYER M5 ;
        RECT  28.272 19.356 28.296 19.44 ;
    END
  END o[166]
  PIN o[167]
    DIRECTION OUTPUT ;
    USE SIGNAL ;
    PORT
      LAYER M5 ;
        RECT  28.368 19.356 28.392 19.44 ;
    END
  END o[167]
  PIN o[168]
    DIRECTION OUTPUT ;
    USE SIGNAL ;
    PORT
      LAYER M5 ;
        RECT  28.464 19.356 28.488 19.44 ;
    END
  END o[168]
  PIN o[169]
    DIRECTION OUTPUT ;
    USE SIGNAL ;
    PORT
      LAYER M5 ;
        RECT  28.56 19.356 28.584 19.44 ;
    END
  END o[169]
  PIN o[16]
    DIRECTION OUTPUT ;
    USE SIGNAL ;
    PORT
      LAYER M5 ;
        RECT  20.016 19.356 20.04 19.44 ;
    END
  END o[16]
  PIN o[170]
    DIRECTION OUTPUT ;
    USE SIGNAL ;
    PORT
      LAYER M5 ;
        RECT  28.656 19.356 28.68 19.44 ;
    END
  END o[170]
  PIN o[171]
    DIRECTION OUTPUT ;
    USE SIGNAL ;
    PORT
      LAYER M5 ;
        RECT  28.752 19.356 28.776 19.44 ;
    END
  END o[171]
  PIN o[172]
    DIRECTION OUTPUT ;
    USE SIGNAL ;
    PORT
      LAYER M5 ;
        RECT  28.848 19.356 28.872 19.44 ;
    END
  END o[172]
  PIN o[173]
    DIRECTION OUTPUT ;
    USE SIGNAL ;
    PORT
      LAYER M5 ;
        RECT  28.944 19.356 28.968 19.44 ;
    END
  END o[173]
  PIN o[174]
    DIRECTION OUTPUT ;
    USE SIGNAL ;
    PORT
      LAYER M5 ;
        RECT  29.04 19.356 29.064 19.44 ;
    END
  END o[174]
  PIN o[175]
    DIRECTION OUTPUT ;
    USE SIGNAL ;
    PORT
      LAYER M5 ;
        RECT  29.136 19.356 29.16 19.44 ;
    END
  END o[175]
  PIN o[176]
    DIRECTION OUTPUT ;
    USE SIGNAL ;
    PORT
      LAYER M5 ;
        RECT  29.232 19.356 29.256 19.44 ;
    END
  END o[176]
  PIN o[177]
    DIRECTION OUTPUT ;
    USE SIGNAL ;
    PORT
      LAYER M5 ;
        RECT  29.328 19.356 29.352 19.44 ;
    END
  END o[177]
  PIN o[178]
    DIRECTION OUTPUT ;
    USE SIGNAL ;
    PORT
      LAYER M5 ;
        RECT  29.424 19.356 29.448 19.44 ;
    END
  END o[178]
  PIN o[179]
    DIRECTION OUTPUT ;
    USE SIGNAL ;
    PORT
      LAYER M5 ;
        RECT  29.52 19.356 29.544 19.44 ;
    END
  END o[179]
  PIN o[17]
    DIRECTION OUTPUT ;
    USE SIGNAL ;
    PORT
      LAYER M5 ;
        RECT  20.112 19.356 20.136 19.44 ;
    END
  END o[17]
  PIN o[180]
    DIRECTION OUTPUT ;
    USE SIGNAL ;
    PORT
      LAYER M5 ;
        RECT  29.616 19.356 29.64 19.44 ;
    END
  END o[180]
  PIN o[181]
    DIRECTION OUTPUT ;
    USE SIGNAL ;
    PORT
      LAYER M5 ;
        RECT  29.712 19.356 29.736 19.44 ;
    END
  END o[181]
  PIN o[182]
    DIRECTION OUTPUT ;
    USE SIGNAL ;
    PORT
      LAYER M5 ;
        RECT  29.808 19.356 29.832 19.44 ;
    END
  END o[182]
  PIN o[183]
    DIRECTION OUTPUT ;
    USE SIGNAL ;
    PORT
      LAYER M5 ;
        RECT  29.904 19.356 29.928 19.44 ;
    END
  END o[183]
  PIN o[184]
    DIRECTION OUTPUT ;
    USE SIGNAL ;
    PORT
      LAYER M5 ;
        RECT  30 19.356 30.024 19.44 ;
    END
  END o[184]
  PIN o[185]
    DIRECTION OUTPUT ;
    USE SIGNAL ;
    PORT
      LAYER M5 ;
        RECT  30.096 19.356 30.12 19.44 ;
    END
  END o[185]
  PIN o[186]
    DIRECTION OUTPUT ;
    USE SIGNAL ;
    PORT
      LAYER M5 ;
        RECT  30.192 19.356 30.216 19.44 ;
    END
  END o[186]
  PIN o[187]
    DIRECTION OUTPUT ;
    USE SIGNAL ;
    PORT
      LAYER M5 ;
        RECT  30.288 19.356 30.312 19.44 ;
    END
  END o[187]
  PIN o[188]
    DIRECTION OUTPUT ;
    USE SIGNAL ;
    PORT
      LAYER M5 ;
        RECT  30.384 19.356 30.408 19.44 ;
    END
  END o[188]
  PIN o[189]
    DIRECTION OUTPUT ;
    USE SIGNAL ;
    PORT
      LAYER M5 ;
        RECT  30.48 19.356 30.504 19.44 ;
    END
  END o[189]
  PIN o[18]
    DIRECTION OUTPUT ;
    USE SIGNAL ;
    PORT
      LAYER M5 ;
        RECT  20.208 19.356 20.232 19.44 ;
    END
  END o[18]
  PIN o[190]
    DIRECTION OUTPUT ;
    USE SIGNAL ;
    PORT
      LAYER M5 ;
        RECT  30.576 19.356 30.6 19.44 ;
    END
  END o[190]
  PIN o[191]
    DIRECTION OUTPUT ;
    USE SIGNAL ;
    PORT
      LAYER M5 ;
        RECT  30.672 19.356 30.696 19.44 ;
    END
  END o[191]
  PIN o[192]
    DIRECTION OUTPUT ;
    USE SIGNAL ;
    PORT
      LAYER M5 ;
        RECT  8.496 19.356 8.52 19.44 ;
    END
  END o[192]
  PIN o[193]
    DIRECTION OUTPUT ;
    USE SIGNAL ;
    PORT
      LAYER M5 ;
        RECT  8.592 19.356 8.616 19.44 ;
    END
  END o[193]
  PIN o[194]
    DIRECTION OUTPUT ;
    USE SIGNAL ;
    PORT
      LAYER M5 ;
        RECT  8.688 19.356 8.712 19.44 ;
    END
  END o[194]
  PIN o[195]
    DIRECTION OUTPUT ;
    USE SIGNAL ;
    PORT
      LAYER M5 ;
        RECT  8.784 19.356 8.808 19.44 ;
    END
  END o[195]
  PIN o[196]
    DIRECTION OUTPUT ;
    USE SIGNAL ;
    PORT
      LAYER M5 ;
        RECT  8.88 19.356 8.904 19.44 ;
    END
  END o[196]
  PIN o[197]
    DIRECTION OUTPUT ;
    USE SIGNAL ;
    PORT
      LAYER M5 ;
        RECT  8.976 19.356 9 19.44 ;
    END
  END o[197]
  PIN o[198]
    DIRECTION OUTPUT ;
    USE SIGNAL ;
    PORT
      LAYER M5 ;
        RECT  9.072 19.356 9.096 19.44 ;
    END
  END o[198]
  PIN o[199]
    DIRECTION OUTPUT ;
    USE SIGNAL ;
    PORT
      LAYER M5 ;
        RECT  9.168 19.356 9.192 19.44 ;
    END
  END o[199]
  PIN o[19]
    DIRECTION OUTPUT ;
    USE SIGNAL ;
    PORT
      LAYER M5 ;
        RECT  20.304 19.356 20.328 19.44 ;
    END
  END o[19]
  PIN o[1]
    DIRECTION OUTPUT ;
    USE SIGNAL ;
    PORT
      LAYER M5 ;
        RECT  18.576 19.356 18.6 19.44 ;
    END
  END o[1]
  PIN o[200]
    DIRECTION OUTPUT ;
    USE SIGNAL ;
    PORT
      LAYER M5 ;
        RECT  9.264 19.356 9.288 19.44 ;
    END
  END o[200]
  PIN o[201]
    DIRECTION OUTPUT ;
    USE SIGNAL ;
    PORT
      LAYER M5 ;
        RECT  9.36 19.356 9.384 19.44 ;
    END
  END o[201]
  PIN o[202]
    DIRECTION OUTPUT ;
    USE SIGNAL ;
    PORT
      LAYER M5 ;
        RECT  9.456 19.356 9.48 19.44 ;
    END
  END o[202]
  PIN o[203]
    DIRECTION OUTPUT ;
    USE SIGNAL ;
    PORT
      LAYER M5 ;
        RECT  9.552 19.356 9.576 19.44 ;
    END
  END o[203]
  PIN o[204]
    DIRECTION OUTPUT ;
    USE SIGNAL ;
    PORT
      LAYER M5 ;
        RECT  9.648 19.356 9.672 19.44 ;
    END
  END o[204]
  PIN o[205]
    DIRECTION OUTPUT ;
    USE SIGNAL ;
    PORT
      LAYER M5 ;
        RECT  9.744 19.356 9.768 19.44 ;
    END
  END o[205]
  PIN o[206]
    DIRECTION OUTPUT ;
    USE SIGNAL ;
    PORT
      LAYER M5 ;
        RECT  9.84 19.356 9.864 19.44 ;
    END
  END o[206]
  PIN o[207]
    DIRECTION OUTPUT ;
    USE SIGNAL ;
    PORT
      LAYER M5 ;
        RECT  9.936 19.356 9.96 19.44 ;
    END
  END o[207]
  PIN o[208]
    DIRECTION OUTPUT ;
    USE SIGNAL ;
    PORT
      LAYER M5 ;
        RECT  10.032 19.356 10.056 19.44 ;
    END
  END o[208]
  PIN o[209]
    DIRECTION OUTPUT ;
    USE SIGNAL ;
    PORT
      LAYER M5 ;
        RECT  10.128 19.356 10.152 19.44 ;
    END
  END o[209]
  PIN o[20]
    DIRECTION OUTPUT ;
    USE SIGNAL ;
    PORT
      LAYER M5 ;
        RECT  20.4 19.356 20.424 19.44 ;
    END
  END o[20]
  PIN o[210]
    DIRECTION OUTPUT ;
    USE SIGNAL ;
    PORT
      LAYER M5 ;
        RECT  10.224 19.356 10.248 19.44 ;
    END
  END o[210]
  PIN o[211]
    DIRECTION OUTPUT ;
    USE SIGNAL ;
    PORT
      LAYER M5 ;
        RECT  10.32 19.356 10.344 19.44 ;
    END
  END o[211]
  PIN o[212]
    DIRECTION OUTPUT ;
    USE SIGNAL ;
    PORT
      LAYER M5 ;
        RECT  10.416 19.356 10.44 19.44 ;
    END
  END o[212]
  PIN o[213]
    DIRECTION OUTPUT ;
    USE SIGNAL ;
    PORT
      LAYER M5 ;
        RECT  10.512 19.356 10.536 19.44 ;
    END
  END o[213]
  PIN o[214]
    DIRECTION OUTPUT ;
    USE SIGNAL ;
    PORT
      LAYER M5 ;
        RECT  10.608 19.356 10.632 19.44 ;
    END
  END o[214]
  PIN o[215]
    DIRECTION OUTPUT ;
    USE SIGNAL ;
    PORT
      LAYER M5 ;
        RECT  10.704 19.356 10.728 19.44 ;
    END
  END o[215]
  PIN o[216]
    DIRECTION OUTPUT ;
    USE SIGNAL ;
    PORT
      LAYER M5 ;
        RECT  10.8 19.356 10.824 19.44 ;
    END
  END o[216]
  PIN o[217]
    DIRECTION OUTPUT ;
    USE SIGNAL ;
    PORT
      LAYER M5 ;
        RECT  10.896 19.356 10.92 19.44 ;
    END
  END o[217]
  PIN o[218]
    DIRECTION OUTPUT ;
    USE SIGNAL ;
    PORT
      LAYER M5 ;
        RECT  10.992 19.356 11.016 19.44 ;
    END
  END o[218]
  PIN o[219]
    DIRECTION OUTPUT ;
    USE SIGNAL ;
    PORT
      LAYER M5 ;
        RECT  11.088 19.356 11.112 19.44 ;
    END
  END o[219]
  PIN o[21]
    DIRECTION OUTPUT ;
    USE SIGNAL ;
    PORT
      LAYER M5 ;
        RECT  20.496 19.356 20.52 19.44 ;
    END
  END o[21]
  PIN o[220]
    DIRECTION OUTPUT ;
    USE SIGNAL ;
    PORT
      LAYER M5 ;
        RECT  11.184 19.356 11.208 19.44 ;
    END
  END o[220]
  PIN o[221]
    DIRECTION OUTPUT ;
    USE SIGNAL ;
    PORT
      LAYER M5 ;
        RECT  11.28 19.356 11.304 19.44 ;
    END
  END o[221]
  PIN o[222]
    DIRECTION OUTPUT ;
    USE SIGNAL ;
    PORT
      LAYER M5 ;
        RECT  11.376 19.356 11.4 19.44 ;
    END
  END o[222]
  PIN o[223]
    DIRECTION OUTPUT ;
    USE SIGNAL ;
    PORT
      LAYER M5 ;
        RECT  11.472 19.356 11.496 19.44 ;
    END
  END o[223]
  PIN o[224]
    DIRECTION OUTPUT ;
    USE SIGNAL ;
    PORT
      LAYER M5 ;
        RECT  11.568 19.356 11.592 19.44 ;
    END
  END o[224]
  PIN o[225]
    DIRECTION OUTPUT ;
    USE SIGNAL ;
    PORT
      LAYER M5 ;
        RECT  11.664 19.356 11.688 19.44 ;
    END
  END o[225]
  PIN o[226]
    DIRECTION OUTPUT ;
    USE SIGNAL ;
    PORT
      LAYER M5 ;
        RECT  11.76 19.356 11.784 19.44 ;
    END
  END o[226]
  PIN o[227]
    DIRECTION OUTPUT ;
    USE SIGNAL ;
    PORT
      LAYER M5 ;
        RECT  11.856 19.356 11.88 19.44 ;
    END
  END o[227]
  PIN o[228]
    DIRECTION OUTPUT ;
    USE SIGNAL ;
    PORT
      LAYER M5 ;
        RECT  11.952 19.356 11.976 19.44 ;
    END
  END o[228]
  PIN o[229]
    DIRECTION OUTPUT ;
    USE SIGNAL ;
    PORT
      LAYER M5 ;
        RECT  12.048 19.356 12.072 19.44 ;
    END
  END o[229]
  PIN o[22]
    DIRECTION OUTPUT ;
    USE SIGNAL ;
    PORT
      LAYER M5 ;
        RECT  20.592 19.356 20.616 19.44 ;
    END
  END o[22]
  PIN o[230]
    DIRECTION OUTPUT ;
    USE SIGNAL ;
    PORT
      LAYER M5 ;
        RECT  12.144 19.356 12.168 19.44 ;
    END
  END o[230]
  PIN o[231]
    DIRECTION OUTPUT ;
    USE SIGNAL ;
    PORT
      LAYER M5 ;
        RECT  12.24 19.356 12.264 19.44 ;
    END
  END o[231]
  PIN o[232]
    DIRECTION OUTPUT ;
    USE SIGNAL ;
    PORT
      LAYER M5 ;
        RECT  12.336 19.356 12.36 19.44 ;
    END
  END o[232]
  PIN o[233]
    DIRECTION OUTPUT ;
    USE SIGNAL ;
    PORT
      LAYER M5 ;
        RECT  12.432 19.356 12.456 19.44 ;
    END
  END o[233]
  PIN o[234]
    DIRECTION OUTPUT ;
    USE SIGNAL ;
    PORT
      LAYER M5 ;
        RECT  12.528 19.356 12.552 19.44 ;
    END
  END o[234]
  PIN o[235]
    DIRECTION OUTPUT ;
    USE SIGNAL ;
    PORT
      LAYER M5 ;
        RECT  12.624 19.356 12.648 19.44 ;
    END
  END o[235]
  PIN o[236]
    DIRECTION OUTPUT ;
    USE SIGNAL ;
    PORT
      LAYER M5 ;
        RECT  12.72 19.356 12.744 19.44 ;
    END
  END o[236]
  PIN o[237]
    DIRECTION OUTPUT ;
    USE SIGNAL ;
    PORT
      LAYER M5 ;
        RECT  12.816 19.356 12.84 19.44 ;
    END
  END o[237]
  PIN o[238]
    DIRECTION OUTPUT ;
    USE SIGNAL ;
    PORT
      LAYER M5 ;
        RECT  12.912 19.356 12.936 19.44 ;
    END
  END o[238]
  PIN o[239]
    DIRECTION OUTPUT ;
    USE SIGNAL ;
    PORT
      LAYER M5 ;
        RECT  13.008 19.356 13.032 19.44 ;
    END
  END o[239]
  PIN o[23]
    DIRECTION OUTPUT ;
    USE SIGNAL ;
    PORT
      LAYER M5 ;
        RECT  20.688 19.356 20.712 19.44 ;
    END
  END o[23]
  PIN o[240]
    DIRECTION OUTPUT ;
    USE SIGNAL ;
    PORT
      LAYER M5 ;
        RECT  13.104 19.356 13.128 19.44 ;
    END
  END o[240]
  PIN o[241]
    DIRECTION OUTPUT ;
    USE SIGNAL ;
    PORT
      LAYER M5 ;
        RECT  13.2 19.356 13.224 19.44 ;
    END
  END o[241]
  PIN o[242]
    DIRECTION OUTPUT ;
    USE SIGNAL ;
    PORT
      LAYER M5 ;
        RECT  13.296 19.356 13.32 19.44 ;
    END
  END o[242]
  PIN o[243]
    DIRECTION OUTPUT ;
    USE SIGNAL ;
    PORT
      LAYER M5 ;
        RECT  13.392 19.356 13.416 19.44 ;
    END
  END o[243]
  PIN o[244]
    DIRECTION OUTPUT ;
    USE SIGNAL ;
    PORT
      LAYER M5 ;
        RECT  13.488 19.356 13.512 19.44 ;
    END
  END o[244]
  PIN o[245]
    DIRECTION OUTPUT ;
    USE SIGNAL ;
    PORT
      LAYER M5 ;
        RECT  13.584 19.356 13.608 19.44 ;
    END
  END o[245]
  PIN o[246]
    DIRECTION OUTPUT ;
    USE SIGNAL ;
    PORT
      LAYER M5 ;
        RECT  13.68 19.356 13.704 19.44 ;
    END
  END o[246]
  PIN o[247]
    DIRECTION OUTPUT ;
    USE SIGNAL ;
    PORT
      LAYER M5 ;
        RECT  13.776 19.356 13.8 19.44 ;
    END
  END o[247]
  PIN o[248]
    DIRECTION OUTPUT ;
    USE SIGNAL ;
    PORT
      LAYER M5 ;
        RECT  13.872 19.356 13.896 19.44 ;
    END
  END o[248]
  PIN o[249]
    DIRECTION OUTPUT ;
    USE SIGNAL ;
    PORT
      LAYER M5 ;
        RECT  13.968 19.356 13.992 19.44 ;
    END
  END o[249]
  PIN o[24]
    DIRECTION OUTPUT ;
    USE SIGNAL ;
    PORT
      LAYER M5 ;
        RECT  20.784 19.356 20.808 19.44 ;
    END
  END o[24]
  PIN o[250]
    DIRECTION OUTPUT ;
    USE SIGNAL ;
    PORT
      LAYER M5 ;
        RECT  14.064 19.356 14.088 19.44 ;
    END
  END o[250]
  PIN o[251]
    DIRECTION OUTPUT ;
    USE SIGNAL ;
    PORT
      LAYER M5 ;
        RECT  14.16 19.356 14.184 19.44 ;
    END
  END o[251]
  PIN o[252]
    DIRECTION OUTPUT ;
    USE SIGNAL ;
    PORT
      LAYER M5 ;
        RECT  14.256 19.356 14.28 19.44 ;
    END
  END o[252]
  PIN o[253]
    DIRECTION OUTPUT ;
    USE SIGNAL ;
    PORT
      LAYER M5 ;
        RECT  14.352 19.356 14.376 19.44 ;
    END
  END o[253]
  PIN o[254]
    DIRECTION OUTPUT ;
    USE SIGNAL ;
    PORT
      LAYER M5 ;
        RECT  14.448 19.356 14.472 19.44 ;
    END
  END o[254]
  PIN o[255]
    DIRECTION OUTPUT ;
    USE SIGNAL ;
    PORT
      LAYER M5 ;
        RECT  14.544 19.356 14.568 19.44 ;
    END
  END o[255]
  PIN o[256]
    DIRECTION OUTPUT ;
    USE SIGNAL ;
    PORT
      LAYER M5 ;
        RECT  5.904 19.356 5.928 19.44 ;
    END
  END o[256]
  PIN o[257]
    DIRECTION OUTPUT ;
    USE SIGNAL ;
    PORT
      LAYER M5 ;
        RECT  6 19.356 6.024 19.44 ;
    END
  END o[257]
  PIN o[258]
    DIRECTION OUTPUT ;
    USE SIGNAL ;
    PORT
      LAYER M5 ;
        RECT  6.096 19.356 6.12 19.44 ;
    END
  END o[258]
  PIN o[259]
    DIRECTION OUTPUT ;
    USE SIGNAL ;
    PORT
      LAYER M5 ;
        RECT  6.192 19.356 6.216 19.44 ;
    END
  END o[259]
  PIN o[25]
    DIRECTION OUTPUT ;
    USE SIGNAL ;
    PORT
      LAYER M5 ;
        RECT  20.88 19.356 20.904 19.44 ;
    END
  END o[25]
  PIN o[260]
    DIRECTION OUTPUT ;
    USE SIGNAL ;
    PORT
      LAYER M5 ;
        RECT  6.288 19.356 6.312 19.44 ;
    END
  END o[260]
  PIN o[261]
    DIRECTION OUTPUT ;
    USE SIGNAL ;
    PORT
      LAYER M5 ;
        RECT  6.384 19.356 6.408 19.44 ;
    END
  END o[261]
  PIN o[262]
    DIRECTION OUTPUT ;
    USE SIGNAL ;
    PORT
      LAYER M5 ;
        RECT  6.48 19.356 6.504 19.44 ;
    END
  END o[262]
  PIN o[263]
    DIRECTION OUTPUT ;
    USE SIGNAL ;
    PORT
      LAYER M5 ;
        RECT  6.576 19.356 6.6 19.44 ;
    END
  END o[263]
  PIN o[264]
    DIRECTION OUTPUT ;
    USE SIGNAL ;
    PORT
      LAYER M5 ;
        RECT  6.672 19.356 6.696 19.44 ;
    END
  END o[264]
  PIN o[265]
    DIRECTION OUTPUT ;
    USE SIGNAL ;
    PORT
      LAYER M5 ;
        RECT  6.768 19.356 6.792 19.44 ;
    END
  END o[265]
  PIN o[266]
    DIRECTION OUTPUT ;
    USE SIGNAL ;
    PORT
      LAYER M5 ;
        RECT  6.864 19.356 6.888 19.44 ;
    END
  END o[266]
  PIN o[267]
    DIRECTION OUTPUT ;
    USE SIGNAL ;
    PORT
      LAYER M5 ;
        RECT  6.96 19.356 6.984 19.44 ;
    END
  END o[267]
  PIN o[268]
    DIRECTION OUTPUT ;
    USE SIGNAL ;
    PORT
      LAYER M5 ;
        RECT  7.056 19.356 7.08 19.44 ;
    END
  END o[268]
  PIN o[269]
    DIRECTION OUTPUT ;
    USE SIGNAL ;
    PORT
      LAYER M5 ;
        RECT  7.152 19.356 7.176 19.44 ;
    END
  END o[269]
  PIN o[26]
    DIRECTION OUTPUT ;
    USE SIGNAL ;
    PORT
      LAYER M5 ;
        RECT  20.976 19.356 21 19.44 ;
    END
  END o[26]
  PIN o[270]
    DIRECTION OUTPUT ;
    USE SIGNAL ;
    PORT
      LAYER M5 ;
        RECT  7.248 19.356 7.272 19.44 ;
    END
  END o[270]
  PIN o[271]
    DIRECTION OUTPUT ;
    USE SIGNAL ;
    PORT
      LAYER M5 ;
        RECT  7.344 19.356 7.368 19.44 ;
    END
  END o[271]
  PIN o[272]
    DIRECTION OUTPUT ;
    USE SIGNAL ;
    PORT
      LAYER M5 ;
        RECT  7.44 19.356 7.464 19.44 ;
    END
  END o[272]
  PIN o[273]
    DIRECTION OUTPUT ;
    USE SIGNAL ;
    PORT
      LAYER M5 ;
        RECT  7.536 19.356 7.56 19.44 ;
    END
  END o[273]
  PIN o[274]
    DIRECTION OUTPUT ;
    USE SIGNAL ;
    PORT
      LAYER M5 ;
        RECT  7.632 19.356 7.656 19.44 ;
    END
  END o[274]
  PIN o[275]
    DIRECTION OUTPUT ;
    USE SIGNAL ;
    PORT
      LAYER M5 ;
        RECT  7.728 19.356 7.752 19.44 ;
    END
  END o[275]
  PIN o[276]
    DIRECTION OUTPUT ;
    USE SIGNAL ;
    PORT
      LAYER M5 ;
        RECT  7.824 19.356 7.848 19.44 ;
    END
  END o[276]
  PIN o[277]
    DIRECTION OUTPUT ;
    USE SIGNAL ;
    PORT
      LAYER M5 ;
        RECT  7.92 19.356 7.944 19.44 ;
    END
  END o[277]
  PIN o[278]
    DIRECTION OUTPUT ;
    USE SIGNAL ;
    PORT
      LAYER M5 ;
        RECT  8.016 19.356 8.04 19.44 ;
    END
  END o[278]
  PIN o[279]
    DIRECTION OUTPUT ;
    USE SIGNAL ;
    PORT
      LAYER M5 ;
        RECT  8.112 19.356 8.136 19.44 ;
    END
  END o[279]
  PIN o[27]
    DIRECTION OUTPUT ;
    USE SIGNAL ;
    PORT
      LAYER M5 ;
        RECT  21.072 19.356 21.096 19.44 ;
    END
  END o[27]
  PIN o[280]
    DIRECTION OUTPUT ;
    USE SIGNAL ;
    PORT
      LAYER M5 ;
        RECT  8.208 19.356 8.232 19.44 ;
    END
  END o[280]
  PIN o[281]
    DIRECTION OUTPUT ;
    USE SIGNAL ;
    PORT
      LAYER M5 ;
        RECT  8.304 19.356 8.328 19.44 ;
    END
  END o[281]
  PIN o[282]
    DIRECTION OUTPUT ;
    USE SIGNAL ;
    PORT
      LAYER M5 ;
        RECT  8.4 19.356 8.424 19.44 ;
    END
  END o[282]
  PIN o[28]
    DIRECTION OUTPUT ;
    USE SIGNAL ;
    PORT
      LAYER M5 ;
        RECT  21.168 19.356 21.192 19.44 ;
    END
  END o[28]
  PIN o[29]
    DIRECTION OUTPUT ;
    USE SIGNAL ;
    PORT
      LAYER M5 ;
        RECT  21.264 19.356 21.288 19.44 ;
    END
  END o[29]
  PIN o[2]
    DIRECTION OUTPUT ;
    USE SIGNAL ;
    PORT
      LAYER M5 ;
        RECT  18.672 19.356 18.696 19.44 ;
    END
  END o[2]
  PIN o[30]
    DIRECTION OUTPUT ;
    USE SIGNAL ;
    PORT
      LAYER M5 ;
        RECT  21.36 19.356 21.384 19.44 ;
    END
  END o[30]
  PIN o[31]
    DIRECTION OUTPUT ;
    USE SIGNAL ;
    PORT
      LAYER M5 ;
        RECT  21.456 19.356 21.48 19.44 ;
    END
  END o[31]
  PIN o[32]
    DIRECTION OUTPUT ;
    USE SIGNAL ;
    PORT
      LAYER M5 ;
        RECT  24.624 19.356 24.648 19.44 ;
    END
  END o[32]
  PIN o[33]
    DIRECTION OUTPUT ;
    USE SIGNAL ;
    PORT
      LAYER M5 ;
        RECT  24.72 19.356 24.744 19.44 ;
    END
  END o[33]
  PIN o[34]
    DIRECTION OUTPUT ;
    USE SIGNAL ;
    PORT
      LAYER M5 ;
        RECT  24.816 19.356 24.84 19.44 ;
    END
  END o[34]
  PIN o[35]
    DIRECTION OUTPUT ;
    USE SIGNAL ;
    PORT
      LAYER M5 ;
        RECT  24.912 19.356 24.936 19.44 ;
    END
  END o[35]
  PIN o[36]
    DIRECTION OUTPUT ;
    USE SIGNAL ;
    PORT
      LAYER M5 ;
        RECT  25.008 19.356 25.032 19.44 ;
    END
  END o[36]
  PIN o[37]
    DIRECTION OUTPUT ;
    USE SIGNAL ;
    PORT
      LAYER M5 ;
        RECT  25.104 19.356 25.128 19.44 ;
    END
  END o[37]
  PIN o[38]
    DIRECTION OUTPUT ;
    USE SIGNAL ;
    PORT
      LAYER M5 ;
        RECT  25.2 19.356 25.224 19.44 ;
    END
  END o[38]
  PIN o[39]
    DIRECTION OUTPUT ;
    USE SIGNAL ;
    PORT
      LAYER M5 ;
        RECT  25.296 19.356 25.32 19.44 ;
    END
  END o[39]
  PIN o[3]
    DIRECTION OUTPUT ;
    USE SIGNAL ;
    PORT
      LAYER M5 ;
        RECT  18.768 19.356 18.792 19.44 ;
    END
  END o[3]
  PIN o[40]
    DIRECTION OUTPUT ;
    USE SIGNAL ;
    PORT
      LAYER M5 ;
        RECT  25.392 19.356 25.416 19.44 ;
    END
  END o[40]
  PIN o[41]
    DIRECTION OUTPUT ;
    USE SIGNAL ;
    PORT
      LAYER M5 ;
        RECT  25.488 19.356 25.512 19.44 ;
    END
  END o[41]
  PIN o[42]
    DIRECTION OUTPUT ;
    USE SIGNAL ;
    PORT
      LAYER M5 ;
        RECT  25.584 19.356 25.608 19.44 ;
    END
  END o[42]
  PIN o[43]
    DIRECTION OUTPUT ;
    USE SIGNAL ;
    PORT
      LAYER M5 ;
        RECT  25.68 19.356 25.704 19.44 ;
    END
  END o[43]
  PIN o[44]
    DIRECTION OUTPUT ;
    USE SIGNAL ;
    PORT
      LAYER M5 ;
        RECT  25.776 19.356 25.8 19.44 ;
    END
  END o[44]
  PIN o[45]
    DIRECTION OUTPUT ;
    USE SIGNAL ;
    PORT
      LAYER M5 ;
        RECT  25.872 19.356 25.896 19.44 ;
    END
  END o[45]
  PIN o[46]
    DIRECTION OUTPUT ;
    USE SIGNAL ;
    PORT
      LAYER M5 ;
        RECT  25.968 19.356 25.992 19.44 ;
    END
  END o[46]
  PIN o[47]
    DIRECTION OUTPUT ;
    USE SIGNAL ;
    PORT
      LAYER M5 ;
        RECT  26.064 19.356 26.088 19.44 ;
    END
  END o[47]
  PIN o[48]
    DIRECTION OUTPUT ;
    USE SIGNAL ;
    PORT
      LAYER M5 ;
        RECT  26.16 19.356 26.184 19.44 ;
    END
  END o[48]
  PIN o[49]
    DIRECTION OUTPUT ;
    USE SIGNAL ;
    PORT
      LAYER M5 ;
        RECT  26.256 19.356 26.28 19.44 ;
    END
  END o[49]
  PIN o[4]
    DIRECTION OUTPUT ;
    USE SIGNAL ;
    PORT
      LAYER M5 ;
        RECT  18.864 19.356 18.888 19.44 ;
    END
  END o[4]
  PIN o[50]
    DIRECTION OUTPUT ;
    USE SIGNAL ;
    PORT
      LAYER M5 ;
        RECT  26.352 19.356 26.376 19.44 ;
    END
  END o[50]
  PIN o[51]
    DIRECTION OUTPUT ;
    USE SIGNAL ;
    PORT
      LAYER M5 ;
        RECT  26.448 19.356 26.472 19.44 ;
    END
  END o[51]
  PIN o[52]
    DIRECTION OUTPUT ;
    USE SIGNAL ;
    PORT
      LAYER M5 ;
        RECT  26.544 19.356 26.568 19.44 ;
    END
  END o[52]
  PIN o[53]
    DIRECTION OUTPUT ;
    USE SIGNAL ;
    PORT
      LAYER M5 ;
        RECT  26.64 19.356 26.664 19.44 ;
    END
  END o[53]
  PIN o[54]
    DIRECTION OUTPUT ;
    USE SIGNAL ;
    PORT
      LAYER M5 ;
        RECT  26.736 19.356 26.76 19.44 ;
    END
  END o[54]
  PIN o[55]
    DIRECTION OUTPUT ;
    USE SIGNAL ;
    PORT
      LAYER M5 ;
        RECT  26.832 19.356 26.856 19.44 ;
    END
  END o[55]
  PIN o[56]
    DIRECTION OUTPUT ;
    USE SIGNAL ;
    PORT
      LAYER M5 ;
        RECT  26.928 19.356 26.952 19.44 ;
    END
  END o[56]
  PIN o[57]
    DIRECTION OUTPUT ;
    USE SIGNAL ;
    PORT
      LAYER M5 ;
        RECT  27.024 19.356 27.048 19.44 ;
    END
  END o[57]
  PIN o[58]
    DIRECTION OUTPUT ;
    USE SIGNAL ;
    PORT
      LAYER M5 ;
        RECT  27.12 19.356 27.144 19.44 ;
    END
  END o[58]
  PIN o[59]
    DIRECTION OUTPUT ;
    USE SIGNAL ;
    PORT
      LAYER M5 ;
        RECT  27.216 19.356 27.24 19.44 ;
    END
  END o[59]
  PIN o[5]
    DIRECTION OUTPUT ;
    USE SIGNAL ;
    PORT
      LAYER M5 ;
        RECT  18.96 19.356 18.984 19.44 ;
    END
  END o[5]
  PIN o[60]
    DIRECTION OUTPUT ;
    USE SIGNAL ;
    PORT
      LAYER M5 ;
        RECT  27.312 19.356 27.336 19.44 ;
    END
  END o[60]
  PIN o[61]
    DIRECTION OUTPUT ;
    USE SIGNAL ;
    PORT
      LAYER M5 ;
        RECT  27.408 19.356 27.432 19.44 ;
    END
  END o[61]
  PIN o[62]
    DIRECTION OUTPUT ;
    USE SIGNAL ;
    PORT
      LAYER M5 ;
        RECT  27.504 19.356 27.528 19.44 ;
    END
  END o[62]
  PIN o[63]
    DIRECTION OUTPUT ;
    USE SIGNAL ;
    PORT
      LAYER M5 ;
        RECT  27.6 19.356 27.624 19.44 ;
    END
  END o[63]
  PIN o[64]
    DIRECTION OUTPUT ;
    USE SIGNAL ;
    PORT
      LAYER M5 ;
        RECT  30.768 19.356 30.792 19.44 ;
    END
  END o[64]
  PIN o[65]
    DIRECTION OUTPUT ;
    USE SIGNAL ;
    PORT
      LAYER M5 ;
        RECT  30.864 19.356 30.888 19.44 ;
    END
  END o[65]
  PIN o[66]
    DIRECTION OUTPUT ;
    USE SIGNAL ;
    PORT
      LAYER M5 ;
        RECT  30.96 19.356 30.984 19.44 ;
    END
  END o[66]
  PIN o[67]
    DIRECTION OUTPUT ;
    USE SIGNAL ;
    PORT
      LAYER M5 ;
        RECT  31.056 19.356 31.08 19.44 ;
    END
  END o[67]
  PIN o[68]
    DIRECTION OUTPUT ;
    USE SIGNAL ;
    PORT
      LAYER M5 ;
        RECT  31.152 19.356 31.176 19.44 ;
    END
  END o[68]
  PIN o[69]
    DIRECTION OUTPUT ;
    USE SIGNAL ;
    PORT
      LAYER M5 ;
        RECT  31.248 19.356 31.272 19.44 ;
    END
  END o[69]
  PIN o[6]
    DIRECTION OUTPUT ;
    USE SIGNAL ;
    PORT
      LAYER M5 ;
        RECT  19.056 19.356 19.08 19.44 ;
    END
  END o[6]
  PIN o[70]
    DIRECTION OUTPUT ;
    USE SIGNAL ;
    PORT
      LAYER M5 ;
        RECT  31.344 19.356 31.368 19.44 ;
    END
  END o[70]
  PIN o[71]
    DIRECTION OUTPUT ;
    USE SIGNAL ;
    PORT
      LAYER M5 ;
        RECT  31.44 19.356 31.464 19.44 ;
    END
  END o[71]
  PIN o[72]
    DIRECTION OUTPUT ;
    USE SIGNAL ;
    PORT
      LAYER M5 ;
        RECT  31.536 19.356 31.56 19.44 ;
    END
  END o[72]
  PIN o[73]
    DIRECTION OUTPUT ;
    USE SIGNAL ;
    PORT
      LAYER M5 ;
        RECT  31.632 19.356 31.656 19.44 ;
    END
  END o[73]
  PIN o[74]
    DIRECTION OUTPUT ;
    USE SIGNAL ;
    PORT
      LAYER M5 ;
        RECT  31.728 19.356 31.752 19.44 ;
    END
  END o[74]
  PIN o[75]
    DIRECTION OUTPUT ;
    USE SIGNAL ;
    PORT
      LAYER M5 ;
        RECT  31.824 19.356 31.848 19.44 ;
    END
  END o[75]
  PIN o[76]
    DIRECTION OUTPUT ;
    USE SIGNAL ;
    PORT
      LAYER M5 ;
        RECT  31.92 19.356 31.944 19.44 ;
    END
  END o[76]
  PIN o[77]
    DIRECTION OUTPUT ;
    USE SIGNAL ;
    PORT
      LAYER M5 ;
        RECT  32.016 19.356 32.04 19.44 ;
    END
  END o[77]
  PIN o[78]
    DIRECTION OUTPUT ;
    USE SIGNAL ;
    PORT
      LAYER M5 ;
        RECT  32.112 19.356 32.136 19.44 ;
    END
  END o[78]
  PIN o[79]
    DIRECTION OUTPUT ;
    USE SIGNAL ;
    PORT
      LAYER M5 ;
        RECT  32.208 19.356 32.232 19.44 ;
    END
  END o[79]
  PIN o[7]
    DIRECTION OUTPUT ;
    USE SIGNAL ;
    PORT
      LAYER M5 ;
        RECT  19.152 19.356 19.176 19.44 ;
    END
  END o[7]
  PIN o[80]
    DIRECTION OUTPUT ;
    USE SIGNAL ;
    PORT
      LAYER M5 ;
        RECT  32.304 19.356 32.328 19.44 ;
    END
  END o[80]
  PIN o[81]
    DIRECTION OUTPUT ;
    USE SIGNAL ;
    PORT
      LAYER M5 ;
        RECT  32.4 19.356 32.424 19.44 ;
    END
  END o[81]
  PIN o[82]
    DIRECTION OUTPUT ;
    USE SIGNAL ;
    PORT
      LAYER M5 ;
        RECT  32.496 19.356 32.52 19.44 ;
    END
  END o[82]
  PIN o[83]
    DIRECTION OUTPUT ;
    USE SIGNAL ;
    PORT
      LAYER M5 ;
        RECT  32.592 19.356 32.616 19.44 ;
    END
  END o[83]
  PIN o[84]
    DIRECTION OUTPUT ;
    USE SIGNAL ;
    PORT
      LAYER M5 ;
        RECT  32.688 19.356 32.712 19.44 ;
    END
  END o[84]
  PIN o[85]
    DIRECTION OUTPUT ;
    USE SIGNAL ;
    PORT
      LAYER M5 ;
        RECT  32.784 19.356 32.808 19.44 ;
    END
  END o[85]
  PIN o[86]
    DIRECTION OUTPUT ;
    USE SIGNAL ;
    PORT
      LAYER M5 ;
        RECT  32.88 19.356 32.904 19.44 ;
    END
  END o[86]
  PIN o[87]
    DIRECTION OUTPUT ;
    USE SIGNAL ;
    PORT
      LAYER M5 ;
        RECT  32.976 19.356 33 19.44 ;
    END
  END o[87]
  PIN o[88]
    DIRECTION OUTPUT ;
    USE SIGNAL ;
    PORT
      LAYER M5 ;
        RECT  33.072 19.356 33.096 19.44 ;
    END
  END o[88]
  PIN o[89]
    DIRECTION OUTPUT ;
    USE SIGNAL ;
    PORT
      LAYER M5 ;
        RECT  33.168 19.356 33.192 19.44 ;
    END
  END o[89]
  PIN o[8]
    DIRECTION OUTPUT ;
    USE SIGNAL ;
    PORT
      LAYER M5 ;
        RECT  19.248 19.356 19.272 19.44 ;
    END
  END o[8]
  PIN o[90]
    DIRECTION OUTPUT ;
    USE SIGNAL ;
    PORT
      LAYER M5 ;
        RECT  33.264 19.356 33.288 19.44 ;
    END
  END o[90]
  PIN o[91]
    DIRECTION OUTPUT ;
    USE SIGNAL ;
    PORT
      LAYER M5 ;
        RECT  33.36 19.356 33.384 19.44 ;
    END
  END o[91]
  PIN o[92]
    DIRECTION OUTPUT ;
    USE SIGNAL ;
    PORT
      LAYER M5 ;
        RECT  33.456 19.356 33.48 19.44 ;
    END
  END o[92]
  PIN o[93]
    DIRECTION OUTPUT ;
    USE SIGNAL ;
    PORT
      LAYER M5 ;
        RECT  33.552 19.356 33.576 19.44 ;
    END
  END o[93]
  PIN o[94]
    DIRECTION OUTPUT ;
    USE SIGNAL ;
    PORT
      LAYER M5 ;
        RECT  33.648 19.356 33.672 19.44 ;
    END
  END o[94]
  PIN o[95]
    DIRECTION OUTPUT ;
    USE SIGNAL ;
    PORT
      LAYER M5 ;
        RECT  33.744 19.356 33.768 19.44 ;
    END
  END o[95]
  PIN o[96]
    DIRECTION OUTPUT ;
    USE SIGNAL ;
    PORT
      LAYER M5 ;
        RECT  21.552 19.356 21.576 19.44 ;
    END
  END o[96]
  PIN o[97]
    DIRECTION OUTPUT ;
    USE SIGNAL ;
    PORT
      LAYER M5 ;
        RECT  21.648 19.356 21.672 19.44 ;
    END
  END o[97]
  PIN o[98]
    DIRECTION OUTPUT ;
    USE SIGNAL ;
    PORT
      LAYER M5 ;
        RECT  21.744 19.356 21.768 19.44 ;
    END
  END o[98]
  PIN o[99]
    DIRECTION OUTPUT ;
    USE SIGNAL ;
    PORT
      LAYER M5 ;
        RECT  21.84 19.356 21.864 19.44 ;
    END
  END o[99]
  PIN o[9]
    DIRECTION OUTPUT ;
    USE SIGNAL ;
    PORT
      LAYER M5 ;
        RECT  19.344 19.356 19.368 19.44 ;
    END
  END o[9]
  PIN rs
    DIRECTION INPUT ;
    USE SIGNAL ;
    PORT
      LAYER M4 ;
        RECT  34.476 3.12 34.56 3.144 ;
    END
  END rs
  PIN VDD
    DIRECTION INOUT ;
    USE POWER ;
    PORT
      LAYER M5 ;
        RECT  29.592 2.151 29.712 17.289 ;
        RECT  24.192 2.151 24.312 17.289 ;
        RECT  18.792 2.151 18.912 17.289 ;
        RECT  13.392 2.151 13.512 17.289 ;
        RECT  7.992 2.151 8.112 17.289 ;
        RECT  2.592 2.151 2.712 17.289 ;
    END
  END VDD
  PIN VSS
    DIRECTION INOUT ;
    USE GROUND ;
    PORT
      LAYER M5 ;
        RECT  29.4 2.137 29.52 17.303 ;
        RECT  24 2.137 24.12 17.303 ;
        RECT  18.6 2.137 18.72 17.303 ;
        RECT  13.2 2.137 13.32 17.303 ;
        RECT  7.8 2.137 7.92 17.303 ;
        RECT  2.4 2.137 2.52 17.303 ;
    END
  END VSS
  OBS
    LAYER RVTN ;
     RECT  2.16 2.16 32.4 2.295 ;
     RECT  2.16 2.565 32.4 2.835 ;
     RECT  2.16 3.105 32.4 3.375 ;
     RECT  2.16 3.645 32.4 3.915 ;
     RECT  2.16 4.185 32.4 4.455 ;
     RECT  2.16 4.725 32.4 4.995 ;
     RECT  2.16 5.265 32.4 5.535 ;
     RECT  2.16 5.805 32.4 6.075 ;
     RECT  2.16 6.345 32.4 6.615 ;
     RECT  2.16 6.885 32.4 7.155 ;
     RECT  2.16 7.425 32.4 7.695 ;
     RECT  2.16 7.965 32.4 8.235 ;
     RECT  2.16 8.505 32.4 8.775 ;
     RECT  2.16 9.045 32.4 9.315 ;
     RECT  2.16 9.585 32.4 9.855 ;
     RECT  2.16 10.125 32.4 10.395 ;
     RECT  2.16 10.665 32.4 10.935 ;
     RECT  2.16 11.205 32.4 11.475 ;
     RECT  2.16 11.745 32.4 12.015 ;
     RECT  2.16 12.285 32.4 12.555 ;
     RECT  2.16 12.825 32.4 13.095 ;
     RECT  2.16 13.365 32.4 13.635 ;
     RECT  2.16 13.905 32.4 14.175 ;
     RECT  2.16 14.445 32.4 14.715 ;
     RECT  2.16 14.985 32.4 15.255 ;
     RECT  2.16 15.525 32.4 15.795 ;
     RECT  2.16 16.065 32.4 16.335 ;
     RECT  2.16 16.605 32.4 16.875 ;
     RECT  2.16 17.145 32.4 17.28 ;
    LAYER RVTP ;
     RECT  2.16 2.295 32.4 2.565 ;
     RECT  2.16 2.835 32.4 3.105 ;
     RECT  2.16 3.375 32.4 3.645 ;
     RECT  2.16 3.915 32.4 4.185 ;
     RECT  2.16 4.455 32.4 4.725 ;
     RECT  2.16 4.995 32.4 5.265 ;
     RECT  2.16 5.535 32.4 5.805 ;
     RECT  2.16 6.075 32.4 6.345 ;
     RECT  2.16 6.615 32.4 6.885 ;
     RECT  2.16 7.155 32.4 7.425 ;
     RECT  2.16 7.695 32.4 7.965 ;
     RECT  2.16 8.235 32.4 8.505 ;
     RECT  2.16 8.775 32.4 9.045 ;
     RECT  2.16 9.315 32.4 9.585 ;
     RECT  2.16 9.855 32.4 10.125 ;
     RECT  2.16 10.395 32.4 10.665 ;
     RECT  2.16 10.935 32.4 11.205 ;
     RECT  2.16 11.475 32.4 11.745 ;
     RECT  2.16 12.015 32.4 12.285 ;
     RECT  2.16 12.555 32.4 12.825 ;
     RECT  2.16 13.095 32.4 13.365 ;
     RECT  2.16 13.635 32.4 13.905 ;
     RECT  2.16 14.175 32.4 14.445 ;
     RECT  2.16 14.715 32.4 14.985 ;
     RECT  2.16 15.255 32.4 15.525 ;
     RECT  2.16 15.795 32.4 16.065 ;
     RECT  2.16 16.335 32.4 16.605 ;
     RECT  2.16 16.875 32.4 17.145 ;
    LAYER M1 ;
     RECT  2.16 2.151 32.4 17.289 ;
    LAYER M2 ;
     RECT  1.399 2.232 1.615 2.25 ;
     RECT  1.039 3.852 1.723 3.87 ;
     RECT  1.723 3.852 1.759 4.14 ;
     RECT  1.615 2.106 1.795 2.25 ;
     RECT  1.327 3.042 1.795 3.06 ;
     RECT  1.795 2.106 1.975 3.06 ;
     RECT  1.759 3.852 1.975 4.41 ;
     RECT  1.975 2.106 2.16 4.41 ;
     RECT  2.16 2.106 2.191 17.289 ;
     RECT  2.191 2.034 3.011 17.289 ;
     RECT  3.011 2.151 3.991 17.289 ;
     RECT  3.991 2.034 7.843 17.289 ;
     RECT  7.843 1.998 8.195 17.289 ;
     RECT  8.195 2.034 8.987 17.289 ;
     RECT  8.923 1.152 9.023 1.17 ;
     RECT  5.647 0.036 10.435 0.054 ;
     RECT  8.987 2.106 10.795 17.289 ;
     RECT  10.435 0.036 12.307 0.09 ;
     RECT  10.795 2.034 13.091 17.289 ;
     RECT  13.091 2.106 13.495 17.289 ;
     RECT  13.351 18.774 13.559 18.792 ;
     RECT  13.495 2.106 13.595 17.712 ;
     RECT  13.595 2.106 14.099 17.289 ;
     RECT  12.307 0.036 14.927 0.549 ;
     RECT  15.115 1.152 15.215 1.17 ;
     RECT  14.099 2.151 15.691 17.289 ;
     RECT  14.927 0.036 16.123 0.09 ;
     RECT  16.123 0.036 17.375 0.126 ;
     RECT  15.691 1.998 17.491 17.289 ;
     RECT  17.375 0.072 19.967 0.126 ;
     RECT  19.967 0.108 20.039 0.126 ;
     RECT  17.491 1.962 22.451 17.289 ;
     RECT  22.451 2.034 23.683 17.289 ;
     RECT  23.683 1.998 25.691 17.289 ;
     RECT  25.691 2.034 29.039 17.289 ;
     RECT  32.287 18.774 32.359 18.792 ;
     RECT  32.359 18.702 32.387 18.792 ;
     RECT  29.039 2.151 32.4 17.289 ;
     RECT  32.4 7.938 32.459 16.902 ;
     RECT  32.387 18.702 32.459 18.72 ;
     RECT  32.459 7.938 32.567 11.844 ;
     RECT  32.567 7.938 32.603 11.034 ;
     RECT  32.459 14.796 32.603 16.902 ;
     RECT  32.603 7.938 32.639 10.494 ;
     RECT  32.567 11.826 32.675 11.844 ;
     RECT  32.4 6.966 32.747 6.984 ;
     RECT  32.639 9.594 32.819 10.494 ;
     RECT  32.639 7.938 32.855 8.334 ;
     RECT  32.4 6.156 32.891 6.174 ;
     RECT  32.459 13.104 32.891 14.004 ;
     RECT  32.819 9.594 32.927 9.882 ;
     RECT  32.891 13.104 32.927 13.122 ;
     RECT  32.603 14.796 32.927 16.434 ;
     RECT  32.855 7.938 32.963 7.956 ;
     RECT  32.891 13.914 32.963 14.004 ;
     RECT  32.927 9.594 32.999 9.612 ;
     RECT  32.927 14.796 32.999 15.552 ;
     RECT  32.963 13.986 33.107 14.004 ;
     RECT  32.999 14.796 33.143 15.282 ;
     RECT  32.4 3.348 33.611 3.366 ;
     RECT  33.143 14.796 33.683 14.814 ;
     RECT  32.927 16.416 33.755 16.434 ;
    LAYER M3 ;
     RECT  14.04 0.043 14.058 0.067 ;
     RECT  19.944 0.067 19.962 0.091 ;
     RECT  5.652 0.031 5.67 0.125 ;
     RECT  19.944 0.091 20.034 0.131 ;
     RECT  17.352 0.031 17.37 0.139 ;
     RECT  19.944 0.131 19.962 0.139 ;
     RECT  24.48 0.091 24.498 0.139 ;
     RECT  25.74 0.091 25.758 0.139 ;
     RECT  26.748 0.091 26.766 0.139 ;
     RECT  14.04 0.067 14.346 0.173 ;
     RECT  19.836 0.139 19.962 0.173 ;
     RECT  17.316 0.139 17.37 0.187 ;
     RECT  16.128 0.103 16.146 0.235 ;
     RECT  19.836 0.173 19.854 0.365 ;
     RECT  14.22 0.173 14.346 0.52 ;
     RECT  15.192 0.067 15.21 0.52 ;
     RECT  12.096 0.091 12.114 0.526 ;
     RECT  10.44 0.067 10.458 0.571 ;
     RECT  14.22 0.52 15.21 0.571 ;
     RECT  16.128 0.235 16.362 0.571 ;
     RECT  21.672 0.091 22.41 0.571 ;
     RECT  23.4 0.091 23.418 0.571 ;
     RECT  24.48 0.139 24.894 0.571 ;
     RECT  25.74 0.139 26.766 0.571 ;
     RECT  2.556 0.571 2.574 0.619 ;
     RECT  13.104 0.235 13.122 0.619 ;
     RECT  12.096 0.526 12.33 0.667 ;
     RECT  13.104 0.619 13.158 0.667 ;
     RECT  14.22 0.571 16.362 0.701 ;
     RECT  9.72 0.571 10.458 0.859 ;
     RECT  27.972 0.571 28.566 1.051 ;
     RECT  8.244 0.091 8.262 1.099 ;
     RECT  21.06 0.571 26.766 1.099 ;
     RECT  27.9 1.051 28.566 1.099 ;
     RECT  2.556 0.619 2.79 1.147 ;
     RECT  7.524 1.099 8.262 1.147 ;
     RECT  9 0.859 10.458 1.147 ;
     RECT  18.612 0.283 18.63 1.195 ;
     RECT  19.368 1.147 19.386 1.195 ;
     RECT  2.556 1.147 2.862 1.243 ;
     RECT  15.12 0.701 16.362 1.387 ;
     RECT  17.244 0.187 17.37 1.387 ;
     RECT  7.416 1.147 10.458 1.579 ;
     RECT  11.34 0.571 11.358 1.579 ;
     RECT  7.416 1.579 11.358 1.627 ;
     RECT  12.096 0.667 13.158 1.627 ;
     RECT  2.556 1.243 2.898 1.723 ;
     RECT  7.416 1.627 13.158 1.723 ;
     RECT  14.22 0.701 14.238 1.723 ;
     RECT  15.12 1.387 17.37 1.723 ;
     RECT  18.612 1.195 19.386 1.723 ;
     RECT  21.06 1.099 28.566 1.723 ;
     RECT  15.12 1.723 19.386 1.771 ;
     RECT  21.06 1.723 28.782 2.029 ;
     RECT  1.404 1.723 14.238 2.059 ;
     RECT  15.12 1.771 19.494 2.059 ;
     RECT  20.772 2.029 29.034 2.143 ;
     RECT  1.404 2.059 19.494 2.191 ;
     RECT  1.404 2.191 19.926 2.263 ;
     RECT  20.772 2.143 29.505 2.263 ;
     RECT  1.404 2.263 29.505 2.413 ;
     RECT  1.404 2.413 29.697 2.641 ;
     RECT  1.404 2.641 30.006 2.839 ;
     RECT  1.404 2.839 30.402 2.875 ;
     RECT  1.404 2.875 30.654 2.911 ;
     RECT  1.404 2.911 31.122 2.971 ;
     RECT  1.044 2.971 31.122 3.181 ;
     RECT  32.184 3.109 32.202 3.181 ;
     RECT  1.044 3.181 32.202 3.299 ;
     RECT  33.588 3.115 33.606 3.371 ;
     RECT  1.044 3.299 31.59 3.407 ;
     RECT  1.044 3.407 31.518 3.875 ;
     RECT  1.728 3.875 31.518 4.145 ;
     RECT  1.764 4.145 31.518 4.415 ;
     RECT  2.232 4.415 31.518 5.837 ;
     RECT  2.268 5.837 31.518 5.881 ;
     RECT  2.268 5.881 32.022 6.683 ;
     RECT  2.304 6.683 32.022 6.845 ;
     RECT  2.34 6.845 32.022 6.961 ;
     RECT  32.868 6.151 32.886 6.961 ;
     RECT  2.34 6.961 32.886 7.933 ;
     RECT  2.34 7.933 32.958 8.195 ;
     RECT  2.376 8.195 32.958 9.589 ;
     RECT  2.376 9.589 32.994 12.749 ;
     RECT  3.672 12.749 32.994 13.055 ;
     RECT  2.376 12.749 2.862 13.595 ;
     RECT  4.608 13.055 32.994 13.981 ;
     RECT  4.608 13.981 33.102 14.071 ;
     RECT  2.415 13.595 2.862 14.143 ;
     RECT  3.672 13.055 3.69 14.143 ;
     RECT  2.415 14.143 3.69 14.179 ;
     RECT  4.572 14.071 33.102 14.179 ;
     RECT  2.415 14.179 33.102 14.449 ;
     RECT  2.34 14.449 33.102 14.783 ;
     RECT  2.415 14.783 33.102 14.791 ;
     RECT  2.415 14.791 33.678 16.411 ;
     RECT  2.415 16.411 33.75 16.891 ;
     RECT  2.376 16.891 33.75 16.943 ;
     RECT  2.376 16.943 3.33 17.069 ;
     RECT  2.415 17.069 3.33 17.105 ;
     RECT  4.068 16.943 33.75 17.105 ;
     RECT  5.688 17.105 14.814 17.165 ;
     RECT  3.312 17.105 3.33 17.249 ;
     RECT  4.068 17.105 4.518 17.249 ;
     RECT  2.415 17.105 2.505 17.297 ;
     RECT  5.796 17.165 14.454 17.597 ;
     RECT  5.796 17.597 11.034 17.645 ;
     RECT  11.916 17.597 14.454 17.645 ;
     RECT  16.812 17.105 33.75 17.645 ;
     RECT  16.812 17.645 20.322 17.693 ;
     RECT  24.732 17.645 33.75 17.693 ;
     RECT  16.812 17.693 19.926 17.741 ;
     RECT  6.012 17.645 10.71 17.789 ;
     RECT  24.804 17.693 29.574 18.077 ;
     RECT  19.584 17.741 19.926 18.173 ;
     RECT  28.872 18.077 29.574 18.173 ;
     RECT  7.272 17.789 10.71 18.221 ;
     RECT  15.624 17.105 16.038 18.221 ;
     RECT  19.584 18.173 19.71 18.221 ;
     RECT  21.672 17.645 23.742 18.221 ;
     RECT  30.492 17.693 33.75 18.221 ;
     RECT  8.28 18.221 9.126 18.269 ;
     RECT  10.116 18.221 10.71 18.269 ;
     RECT  15.624 18.221 15.642 18.269 ;
     RECT  16.812 17.741 18.558 18.269 ;
     RECT  21.672 18.221 21.69 18.269 ;
     RECT  30.492 18.221 32.778 18.269 ;
     RECT  17.496 18.269 18.198 18.317 ;
     RECT  7.272 18.221 7.398 18.749 ;
     RECT  7.38 18.749 7.398 18.797 ;
     RECT  8.46 18.269 9.126 18.797 ;
     RECT  10.404 18.269 10.53 18.797 ;
     RECT  11.988 17.645 14.418 18.797 ;
     RECT  17.64 18.317 18.198 18.797 ;
     RECT  19.692 18.221 19.71 18.797 ;
     RECT  24.804 18.077 27.774 18.797 ;
     RECT  32.22 18.269 32.49 18.797 ;
     RECT  33.66 18.221 33.75 18.797 ;
     RECT  6.012 17.789 6.498 18.845 ;
     RECT  11.988 18.797 13.59 18.845 ;
     RECT  17.856 18.797 17.946 18.845 ;
     RECT  22.608 18.221 22.626 18.845 ;
     RECT  32.364 18.797 32.49 18.845 ;
     RECT  32.364 18.845 32.454 18.893 ;
     RECT  32.436 18.893 32.454 18.941 ;
     RECT  6.048 18.845 6.498 18.989 ;
     RECT  25.38 18.797 27.774 19.181 ;
     RECT  28.872 18.173 28.998 19.277 ;
     RECT  6.48 18.989 6.498 19.325 ;
     RECT  8.784 18.797 9.126 19.325 ;
     RECT  13.356 18.845 13.374 19.325 ;
     RECT  17.928 18.845 17.946 19.325 ;
     RECT  23.58 18.221 23.598 19.325 ;
     RECT  25.38 19.181 26.298 19.325 ;
     RECT  27.108 19.181 27.774 19.325 ;
     RECT  28.98 19.277 28.998 19.325 ;
     RECT  30.492 18.269 31.23 19.325 ;
     RECT  33.66 18.797 33.678 19.325 ;
    LAYER M4 ;
     RECT  0.805 2.88 0.901 2.904 ;
     RECT  0.901 2.88 0.989 2.952 ;
     RECT  0.989 2.88 1.072 3 ;
     RECT  1.072 2.88 1.189 3.048 ;
     RECT  1.477 0.576 1.669 0.6 ;
     RECT  1.349 1.728 1.828 1.752 ;
     RECT  0.709 6.288 2.213 6.312 ;
     RECT  1.828 1.728 2.252 1.8 ;
     RECT  1.189 2.88 2.252 4.008 ;
     RECT  2.213 5.712 2.285 6.312 ;
     RECT  1.669 0.576 2.293 0.648 ;
     RECT  2.252 1.728 2.293 4.008 ;
     RECT  2.293 0.144 2.408 4.008 ;
     RECT  2.285 5.136 2.408 6.312 ;
     RECT  2.365 16.896 2.408 16.92 ;
     RECT  2.408 0.144 2.512 17.292 ;
     RECT  2.512 0.144 2.704 17.022 ;
     RECT  2.704 0.144 2.837 2.04 ;
     RECT  2.704 4.176 2.867 5.304 ;
     RECT  2.867 4.176 2.881 5.112 ;
     RECT  2.837 0.144 2.909 1.944 ;
     RECT  2.704 6.288 3.125 6.312 ;
     RECT  2.909 1.728 3.347 1.944 ;
     RECT  2.704 16.896 3.697 16.92 ;
     RECT  2.704 12.288 3.841 12.552 ;
     RECT  2.704 14.352 3.841 14.664 ;
     RECT  2.909 0.144 3.923 0.312 ;
     RECT  3.805 10.608 3.98 10.632 ;
     RECT  3.841 11.76 3.98 12.552 ;
     RECT  3.98 10.032 4.067 10.632 ;
     RECT  3.98 11.664 4.067 12.552 ;
     RECT  3.841 14.352 4.129 14.712 ;
     RECT  3.697 16.032 4.129 16.92 ;
     RECT  4.129 14.352 4.241 16.92 ;
     RECT  3.985 7.104 4.381 7.128 ;
     RECT  4.067 11.712 4.597 12.552 ;
     RECT  3.877 2.88 4.601 2.904 ;
     RECT  4.241 14.352 4.601 16.056 ;
     RECT  2.881 4.176 4.669 4.2 ;
     RECT  4.381 7.104 4.693 8.088 ;
     RECT  4.693 7.104 4.78 8.76 ;
     RECT  3.347 1.728 4.933 1.896 ;
     RECT  4.597 11.712 5.029 13.128 ;
     RECT  4.669 3.936 5.077 4.2 ;
     RECT  4.78 7.104 5.101 8.088 ;
     RECT  4.067 10.08 5.101 10.104 ;
     RECT  4.601 14.64 5.177 16.056 ;
     RECT  5.101 7.056 5.321 8.088 ;
     RECT  5.321 7.056 5.353 8.04 ;
     RECT  5.077 3.936 5.389 4.824 ;
     RECT  5.101 10.08 5.389 10.728 ;
     RECT  5.029 11.712 5.389 13.608 ;
     RECT  5.389 3.84 5.533 4.824 ;
     RECT  4.933 1.728 5.569 2.664 ;
     RECT  5.533 3.84 5.569 5.592 ;
     RECT  5.569 1.728 5.677 5.592 ;
     RECT  5.353 6.576 5.677 8.04 ;
     RECT  5.597 0.096 5.681 0.12 ;
     RECT  5.677 17.136 5.785 17.16 ;
     RECT  5.177 16.032 5.825 16.056 ;
     RECT  5.785 17.136 5.948 17.64 ;
     RECT  5.389 10.08 6.001 13.608 ;
     RECT  6.001 18.816 6.037 18.84 ;
     RECT  5.677 1.728 6.325 8.04 ;
     RECT  6.001 10.032 6.325 13.608 ;
     RECT  5.177 14.64 6.325 14.712 ;
     RECT  6.037 18.816 6.373 18.984 ;
     RECT  6.373 18.816 6.509 19.32 ;
     RECT  6.509 18.816 6.707 18.984 ;
     RECT  6.325 1.728 6.757 8.472 ;
     RECT  5.948 17.088 6.865 17.64 ;
     RECT  6.865 17.088 7.009 17.784 ;
     RECT  6.757 1.728 7.189 8.52 ;
     RECT  7.009 16.512 7.217 17.784 ;
     RECT  6.853 18.768 7.217 18.792 ;
     RECT  7.217 16.512 7.333 18.792 ;
     RECT  7.189 1.728 7.381 9.048 ;
     RECT  6.325 10.032 7.381 14.712 ;
     RECT  7.333 16.272 7.381 18.792 ;
     RECT  7.381 1.728 7.405 14.712 ;
     RECT  7.405 1.152 7.477 14.76 ;
     RECT  7.381 15.984 7.477 18.792 ;
     RECT  7.477 1.152 7.488 18.792 ;
     RECT  7.488 1.104 7.669 18.792 ;
     RECT  7.669 1.104 8.104 19.272 ;
     RECT  8.104 1.104 8.489 15.096 ;
     RECT  8.104 16.176 8.489 19.272 ;
     RECT  8.489 16.176 8.525 18.216 ;
     RECT  8.489 19.248 8.581 19.272 ;
     RECT  8.233 0.096 8.917 0.12 ;
     RECT  8.917 0.048 8.989 0.12 ;
     RECT  8.489 1.104 8.989 14.808 ;
     RECT  8.581 19.248 9.029 19.32 ;
     RECT  9.029 19.296 9.137 19.32 ;
     RECT  8.525 16.176 9.317 16.632 ;
     RECT  9.317 16.56 9.461 16.632 ;
     RECT  8.525 17.616 9.521 18.216 ;
     RECT  8.989 0.048 9.673 14.808 ;
     RECT  9.521 17.088 9.683 18.216 ;
     RECT  9.683 17.568 9.829 18.216 ;
     RECT  9.829 17.568 10.309 18.264 ;
     RECT  10.309 17.568 10.585 18.792 ;
     RECT  10.585 17.568 10.673 18.264 ;
     RECT  10.673 17.088 10.721 18.264 ;
     RECT  10.721 17.088 10.781 17.64 ;
     RECT  9.673 0.048 10.901 15.384 ;
     RECT  10.901 14.208 10.933 15.384 ;
     RECT  10.781 16.512 10.933 17.64 ;
     RECT  11.977 18.816 12.277 18.84 ;
     RECT  10.901 0.048 12.589 13.128 ;
     RECT  12.589 0.048 12.661 13.176 ;
     RECT  10.933 14.208 12.661 17.64 ;
     RECT  12.277 18.72 13.189 18.84 ;
     RECT  13.189 18.672 13.285 18.84 ;
     RECT  13.285 18.672 13.385 19.32 ;
     RECT  13.385 18.72 13.619 18.84 ;
     RECT  13.619 18.72 13.997 18.792 ;
     RECT  12.661 0.048 14.003 17.64 ;
     RECT  14.003 0.048 14.069 15.72 ;
     RECT  14.003 16.992 14.221 17.64 ;
     RECT  14.069 0.096 14.401 15.72 ;
     RECT  14.221 17.088 14.428 17.64 ;
     RECT  13.997 18.768 14.429 18.792 ;
     RECT  14.428 17.136 14.509 17.64 ;
     RECT  14.401 0.192 14.825 15.72 ;
     RECT  14.509 17.136 14.825 17.16 ;
     RECT  14.825 1.632 14.867 15.72 ;
     RECT  14.867 1.728 15.325 15.72 ;
     RECT  14.825 0.192 15.443 0.648 ;
     RECT  15.325 1.728 15.443 16.008 ;
     RECT  15.443 0.24 15.635 0.648 ;
     RECT  15.577 16.416 15.932 17.064 ;
     RECT  15.493 18.24 15.932 18.264 ;
     RECT  15.635 0.24 16.057 0.6 ;
     RECT  15.932 16.416 16.373 18.264 ;
     RECT  15.443 1.728 16.657 15.432 ;
     RECT  16.657 1.392 16.933 15.432 ;
     RECT  16.373 16.56 16.985 18.264 ;
     RECT  16.057 0.24 17.233 0.264 ;
     RECT  17.233 0.192 17.305 0.264 ;
     RECT  16.985 17.088 17.317 18.264 ;
     RECT  17.317 17.088 17.701 18.792 ;
     RECT  16.933 1.392 17.893 15.576 ;
     RECT  17.701 17.088 17.957 19.32 ;
     RECT  17.893 1.392 18.053 16.008 ;
     RECT  17.957 17.088 18.227 18.84 ;
     RECT  18.053 1.392 18.373 16.104 ;
     RECT  18.227 17.088 18.373 18.264 ;
     RECT  18.373 1.392 18.569 18.264 ;
     RECT  17.305 0.144 18.601 0.264 ;
     RECT  18.601 0.144 19.285 0.312 ;
     RECT  18.569 1.392 19.285 18.216 ;
     RECT  19.285 0.144 19.621 18.216 ;
     RECT  19.621 0.144 19.721 18.792 ;
     RECT  19.721 0.144 19.937 18.168 ;
     RECT  19.937 0.144 20.005 17.688 ;
     RECT  20.005 0.096 20.089 17.688 ;
     RECT  20.089 0.144 20.147 17.688 ;
     RECT  20.147 0.192 20.153 17.688 ;
     RECT  20.153 0.192 20.189 15.432 ;
     RECT  20.153 16.512 20.333 17.688 ;
     RECT  20.189 0.192 20.435 13.128 ;
     RECT  20.189 14.112 20.449 15.432 ;
     RECT  20.435 0.192 21.409 1.224 ;
     RECT  20.435 2.304 21.409 13.128 ;
     RECT  21.409 0.192 21.421 13.128 ;
     RECT  21.421 1.728 21.589 13.128 ;
     RECT  20.449 14.112 21.589 15.192 ;
     RECT  21.421 0.192 21.617 0.6 ;
     RECT  20.333 16.512 21.637 17.64 ;
     RECT  21.589 1.728 21.673 15.192 ;
     RECT  21.637 16.512 21.769 18.264 ;
     RECT  21.673 14.112 21.877 15.192 ;
     RECT  21.769 16.32 21.877 18.264 ;
     RECT  21.673 1.728 21.923 13.128 ;
     RECT  21.877 14.112 22.205 18.264 ;
     RECT  21.923 1.728 22.259 12.84 ;
     RECT  22.205 16.272 22.556 18.264 ;
     RECT  22.556 16.272 22.643 18.84 ;
     RECT  21.617 0.096 22.769 0.6 ;
     RECT  22.259 1.728 22.769 8.712 ;
     RECT  22.259 9.696 23.101 12.84 ;
     RECT  23.101 9.696 23.365 13.08 ;
     RECT  23.525 19.296 23.609 19.32 ;
     RECT  23.365 9.696 23.641 13.128 ;
     RECT  22.205 14.112 23.641 14.952 ;
     RECT  23.641 9.696 23.677 14.952 ;
     RECT  22.643 16.272 23.677 18.216 ;
     RECT  23.677 9.696 23.753 18.216 ;
     RECT  22.769 0.096 24.008 8.712 ;
     RECT  23.753 9.696 24.008 17.688 ;
     RECT  24.008 0.096 24.304 17.688 ;
     RECT  24.304 14.112 24.509 15 ;
     RECT  24.304 15.984 24.563 17.688 ;
     RECT  24.304 0.096 24.659 8.712 ;
     RECT  23.941 19.248 24.793 19.272 ;
     RECT  24.563 17.088 24.797 17.688 ;
     RECT  24.797 17.568 24.901 17.688 ;
     RECT  24.793 18.768 24.901 19.272 ;
     RECT  24.901 17.568 25.285 19.272 ;
     RECT  24.304 10.08 25.333 13.08 ;
     RECT  25.333 10.08 25.381 13.128 ;
     RECT  25.285 17.568 25.445 19.32 ;
     RECT  24.659 1.728 25.477 8.712 ;
     RECT  25.381 9.984 25.477 13.128 ;
     RECT  25.477 1.728 25.523 13.128 ;
     RECT  24.563 15.984 25.525 16.008 ;
     RECT  25.445 18.768 25.553 19.32 ;
     RECT  24.509 14.112 25.573 14.952 ;
     RECT  25.523 2.304 25.625 13.128 ;
     RECT  25.621 16.56 25.705 16.584 ;
     RECT  25.445 17.568 25.957 17.736 ;
     RECT  24.659 0.096 26.053 0.6 ;
     RECT  25.957 17.088 26.165 17.736 ;
     RECT  26.165 17.088 26.236 17.208 ;
     RECT  25.573 14.112 26.269 15.432 ;
     RECT  26.053 0.096 26.485 1.176 ;
     RECT  25.625 2.304 26.485 12.312 ;
     RECT  26.485 0.096 26.701 12.312 ;
     RECT  26.269 13.344 26.701 15.432 ;
     RECT  25.553 19.104 26.809 19.32 ;
     RECT  26.809 18.192 26.893 19.32 ;
     RECT  26.236 17.088 27.013 17.16 ;
     RECT  26.701 0.096 27.029 15.432 ;
     RECT  27.029 0.096 27.059 10.296 ;
     RECT  27.013 16.56 27.109 17.16 ;
     RECT  27.109 16.512 27.205 17.16 ;
     RECT  27.029 11.664 27.313 15.432 ;
     RECT  27.059 0.576 27.317 10.296 ;
     RECT  27.313 11.664 27.635 15.48 ;
     RECT  27.317 9.936 27.713 10.296 ;
     RECT  26.893 18.768 27.731 19.32 ;
     RECT  27.731 19.152 27.785 19.32 ;
     RECT  27.205 16.512 28.069 17.592 ;
     RECT  27.635 12 28.165 15.48 ;
     RECT  28.069 16.512 28.165 17.688 ;
     RECT  28.165 12 28.393 17.688 ;
     RECT  27.317 0.576 28.621 8.856 ;
     RECT  28.621 1.104 28.691 8.856 ;
     RECT  28.691 1.728 28.793 8.856 ;
     RECT  27.785 19.152 28.817 19.176 ;
     RECT  28.793 2.148 28.837 8.856 ;
     RECT  27.713 10.272 28.837 10.296 ;
     RECT  28.837 2.148 28.897 10.296 ;
     RECT  28.393 12 28.897 18.072 ;
     RECT  28.817 19.152 28.925 19.272 ;
     RECT  28.925 19.152 28.979 19.32 ;
     RECT  28.979 19.248 29.009 19.32 ;
     RECT  29.009 19.248 29.363 19.272 ;
     RECT  28.897 2.148 29.413 18.072 ;
     RECT  29.413 2.148 29.512 18.168 ;
     RECT  29.512 2.418 29.585 18.168 ;
     RECT  29.585 2.418 29.704 17.688 ;
     RECT  29.704 3.024 29.801 3.432 ;
     RECT  29.801 3.024 29.843 3.144 ;
     RECT  29.704 4.944 29.953 6.84 ;
     RECT  29.704 14.928 29.981 17.688 ;
     RECT  29.704 11.952 30.017 13.848 ;
     RECT  29.981 16.464 30.035 17.688 ;
     RECT  29.953 4.944 30.233 6.024 ;
     RECT  30.017 11.952 30.305 13.128 ;
     RECT  30.233 4.944 30.341 5.688 ;
     RECT  30.341 5.472 30.413 5.688 ;
     RECT  30.305 11.952 30.515 12.6 ;
     RECT  29.981 14.928 30.515 15.48 ;
     RECT  30.515 12.48 30.593 12.6 ;
     RECT  29.704 10.176 30.701 10.968 ;
     RECT  30.437 19.296 30.757 19.32 ;
     RECT  29.704 8.16 30.805 9.048 ;
     RECT  30.805 7.968 30.917 9.048 ;
     RECT  30.757 18.768 30.953 19.32 ;
     RECT  30.035 16.464 30.997 17.64 ;
     RECT  30.413 5.664 31.069 5.688 ;
     RECT  30.949 11.184 31.097 11.208 ;
     RECT  30.997 15.984 31.196 17.64 ;
     RECT  30.917 7.968 31.205 8.952 ;
     RECT  31.205 7.968 31.237 8.472 ;
     RECT  30.701 10.176 31.241 10.2 ;
     RECT  30.953 19.296 31.241 19.32 ;
     RECT  31.165 14.832 31.249 14.856 ;
     RECT  31.237 7.392 31.321 8.472 ;
     RECT  31.201 13.632 31.349 13.656 ;
     RECT  30.593 12.528 31.453 12.6 ;
     RECT  31.453 12.528 31.565 13.272 ;
     RECT  31.565 13.056 31.817 13.272 ;
     RECT  31.196 15.984 31.907 18.264 ;
     RECT  31.321 7.968 31.948 8.472 ;
     RECT  31.907 15.984 32.029 16.008 ;
     RECT  31.907 17.04 32.165 18.264 ;
     RECT  31.948 7.968 32.329 7.992 ;
     RECT  31.817 13.056 32.339 13.08 ;
     RECT  32.165 17.04 32.353 18.792 ;
     RECT  32.353 17.04 32.425 18.888 ;
     RECT  32.029 15.408 32.677 16.008 ;
     RECT  32.425 17.04 32.681 18.936 ;
     RECT  32.677 15.36 32.761 16.008 ;
     RECT  32.761 15.408 32.819 16.008 ;
     RECT  32.681 17.616 32.915 18.936 ;
     RECT  32.915 17.664 33.107 18.936 ;
     RECT  32.819 15.408 33.203 15.432 ;
     RECT  29.843 3.024 33.577 3.048 ;
     RECT  33.107 17.664 33.587 17.688 ;
     RECT  33.107 18.768 33.605 18.936 ;
     RECT  33.605 18.768 33.689 19.32 ;
     RECT  33.689 18.768 33.805 18.792 ;
     RECT  33.577 3.024 34.524 3.144 ;
    LAYER M5 ;
     RECT  0.72 0.016 29.064 0.323 ;
     RECT  20.208 0.323 29.064 1.811 ;
     RECT  20.208 1.811 24.312 1.859 ;
     RECT  0.72 0.323 19.08 1.907 ;
     RECT  4.944 1.907 19.08 1.955 ;
     RECT  5.04 1.955 5.064 2.051 ;
     RECT  27.312 1.811 29.064 2.137 ;
     RECT  27.312 2.137 29.52 2.151 ;
     RECT  6.192 1.955 19.08 2.291 ;
     RECT  27.312 2.151 29.712 2.291 ;
     RECT  20.208 1.859 22.152 2.339 ;
     RECT  25.632 1.811 26.28 2.339 ;
     RECT  6.192 2.291 17.112 2.579 ;
     RECT  28.944 2.291 29.712 2.867 ;
     RECT  0.72 1.907 3.912 2.915 ;
     RECT  21.648 2.339 22.152 2.915 ;
     RECT  0.72 2.915 2.952 3.011 ;
     RECT  14.64 2.579 17.112 3.011 ;
     RECT  24 1.859 24.312 3.013 ;
     RECT  29.4 2.867 29.712 3.013 ;
     RECT  14.64 3.011 16.872 3.059 ;
     RECT  15.024 3.059 16.872 3.155 ;
     RECT  24 3.013 24.408 3.155 ;
     RECT  29.4 3.013 29.832 3.155 ;
     RECT  20.208 2.339 20.52 3.443 ;
     RECT  21.648 2.915 21.672 3.443 ;
     RECT  27.312 2.291 27.72 3.443 ;
     RECT  27.312 3.443 27.384 3.539 ;
     RECT  0.72 3.011 1.224 4.019 ;
     RECT  27.36 3.539 27.384 4.115 ;
     RECT  20.304 3.443 20.52 4.163 ;
     RECT  5.088 3.925 5.112 4.213 ;
     RECT  6.192 2.579 13.656 4.213 ;
     RECT  5.088 4.213 13.656 4.691 ;
     RECT  15.792 3.155 16.872 4.739 ;
     RECT  5.088 4.691 13.512 4.835 ;
     RECT  24 3.155 24.312 5.077 ;
     RECT  16.272 4.739 16.872 5.125 ;
     RECT  5.808 4.835 13.512 5.603 ;
     RECT  20.496 4.163 20.52 5.653 ;
     RECT  23.28 5.077 24.312 5.699 ;
     RECT  2.256 3.011 2.952 5.747 ;
     RECT  6.288 5.603 13.512 5.747 ;
     RECT  20.496 5.653 21 5.749 ;
     RECT  25.632 2.339 25.656 5.795 ;
     RECT  6.816 5.747 13.512 5.987 ;
     RECT  20.256 5.749 21 5.989 ;
     RECT  6.816 5.987 10.584 6.035 ;
     RECT  20.16 5.989 21 6.131 ;
     RECT  0.72 4.019 0.744 6.323 ;
     RECT  2.4 5.747 2.952 6.323 ;
     RECT  16.272 5.125 17.064 6.323 ;
     RECT  11.952 5.987 13.512 6.805 ;
     RECT  24 5.699 24.312 6.805 ;
     RECT  29.4 3.155 29.712 6.805 ;
     RECT  6.816 6.035 9 6.995 ;
     RECT  11.952 6.805 14.376 7.381 ;
     RECT  31.008 5.653 31.032 7.381 ;
     RECT  24 6.805 24.408 7.427 ;
     RECT  11.952 7.381 14.664 7.669 ;
     RECT  11.952 7.669 14.952 7.909 ;
     RECT  20.4 6.131 21 7.957 ;
     RECT  5.04 7.861 5.064 8.053 ;
     RECT  27.84 5.893 27.864 8.435 ;
     RECT  6.816 6.995 8.952 8.437 ;
     RECT  25.68 8.389 25.704 8.437 ;
     RECT  31.008 7.381 31.272 8.437 ;
     RECT  32.256 7.957 32.28 8.437 ;
     RECT  6.336 8.437 8.952 8.483 ;
     RECT  16.272 6.323 16.296 8.485 ;
     RECT  29.4 6.805 29.928 8.485 ;
     RECT  11.952 7.909 15.144 8.533 ;
     RECT  4.704 8.053 5.064 8.771 ;
     RECT  10.08 6.035 10.584 8.869 ;
     RECT  11.664 8.533 15.144 8.869 ;
     RECT  10.08 8.869 15.144 8.915 ;
     RECT  10.08 8.915 14.952 9.059 ;
     RECT  18.6 2.291 18.912 9.061 ;
     RECT  7.392 8.483 8.952 9.109 ;
     RECT  10.08 9.059 10.584 9.109 ;
     RECT  16.272 8.485 17.112 9.109 ;
     RECT  20.4 7.957 21.24 9.109 ;
     RECT  11.664 9.059 14.952 9.155 ;
     RECT  16.128 9.109 17.112 9.347 ;
     RECT  16.128 9.347 16.152 9.491 ;
     RECT  7.392 9.109 10.584 9.683 ;
     RECT  25.392 8.437 25.704 10.019 ;
     RECT  24 7.427 24.312 10.117 ;
     RECT  25.488 10.019 25.704 10.165 ;
     RECT  10.224 9.683 10.584 10.261 ;
     RECT  11.952 9.155 14.952 10.261 ;
     RECT  10.224 10.261 14.952 10.307 ;
     RECT  25.488 10.165 26.376 10.309 ;
     RECT  22.224 8.341 22.248 10.403 ;
     RECT  28.656 8.485 29.928 10.741 ;
     RECT  31.008 8.437 32.28 10.741 ;
     RECT  24 10.117 24.408 10.835 ;
     RECT  10.224 10.307 11.208 10.979 ;
     RECT  18.384 9.061 18.912 11.125 ;
     RECT  20.304 9.109 21.24 11.125 ;
     RECT  7.392 9.683 8.952 11.365 ;
     RECT  24 10.835 24.312 11.365 ;
     RECT  11.184 10.979 11.208 11.605 ;
     RECT  12.24 10.307 14.952 11.605 ;
     RECT  7.392 11.365 9.72 11.651 ;
     RECT  4.032 10.021 4.056 11.699 ;
     RECT  25.488 10.309 26.472 11.941 ;
     RECT  27.6 10.261 27.624 11.941 ;
     RECT  5.04 8.771 5.064 11.989 ;
     RECT  23.376 11.365 24.312 12.181 ;
     RECT  25.488 11.941 27.624 12.517 ;
     RECT  28.656 10.741 32.28 12.517 ;
     RECT  5.04 11.989 5.16 12.563 ;
     RECT  23.184 12.181 24.312 12.613 ;
     RECT  25.488 12.517 32.28 12.613 ;
     RECT  23.184 12.613 32.28 13.045 ;
     RECT  7.392 11.651 8.952 13.093 ;
     RECT  18.384 11.125 21.24 13.093 ;
     RECT  5.04 12.563 5.064 13.139 ;
     RECT  16.224 13.045 16.248 13.141 ;
     RECT  17.28 12.901 17.304 13.141 ;
     RECT  7.392 13.093 9.384 13.189 ;
     RECT  11.184 11.605 14.952 13.189 ;
     RECT  16.224 13.141 17.304 13.189 ;
     RECT  16.128 13.189 17.304 13.331 ;
     RECT  16.224 13.331 17.304 13.525 ;
     RECT  18.384 13.093 21.912 13.525 ;
     RECT  7.392 13.189 14.952 13.667 ;
     RECT  6.336 8.483 6.36 13.859 ;
     RECT  11.184 13.667 14.952 14.291 ;
     RECT  23.136 13.045 32.328 14.291 ;
     RECT  11.184 14.291 13.656 14.821 ;
     RECT  28.176 14.291 32.328 15.349 ;
     RECT  28.176 15.349 32.712 15.397 ;
     RECT  14.928 14.291 14.952 15.443 ;
     RECT  16.224 13.525 21.912 15.443 ;
     RECT  11.088 14.821 13.656 15.589 ;
     RECT  11.088 15.589 14.376 15.731 ;
     RECT  23.136 14.291 26.52 16.019 ;
     RECT  28.176 15.397 33.192 16.067 ;
     RECT  7.392 13.667 9.96 16.261 ;
     RECT  15.408 15.973 15.432 16.405 ;
     RECT  16.56 15.443 20.136 16.405 ;
     RECT  7.344 16.261 9.96 16.501 ;
     RECT  11.088 15.731 13.992 16.501 ;
     RECT  15.408 16.405 20.136 16.501 ;
     RECT  21.216 15.443 21.48 16.501 ;
     RECT  25.584 16.019 26.52 16.501 ;
     RECT  7.344 16.501 13.992 16.981 ;
     RECT  23.136 16.019 24.552 17.029 ;
     RECT  25.584 16.501 27.144 17.029 ;
     RECT  28.368 16.067 33.192 17.029 ;
     RECT  7.344 16.981 14.184 17.077 ;
     RECT  15.408 16.501 21.48 17.077 ;
     RECT  22.992 17.029 24.552 17.077 ;
     RECT  25.584 17.029 33.192 17.077 ;
     RECT  6 17.077 14.376 17.125 ;
     RECT  15.408 17.077 33.192 17.125 ;
     RECT  2.4 6.323 2.712 17.289 ;
     RECT  2.4 17.289 2.52 17.303 ;
     RECT  6 17.125 33.192 17.605 ;
     RECT  5.904 17.605 33.192 17.653 ;
     RECT  5.904 17.653 33.576 18.757 ;
     RECT  5.904 18.757 33.768 19.408 ;
  END
END dsfd_rly_283_SN
END LIBRARY
